VERSION 5.7 ;
  NOWIREEXTENSIONATPIN ON ;
  DIVIDERCHAR "/" ;
  BUSBITCHARS "[]" ;
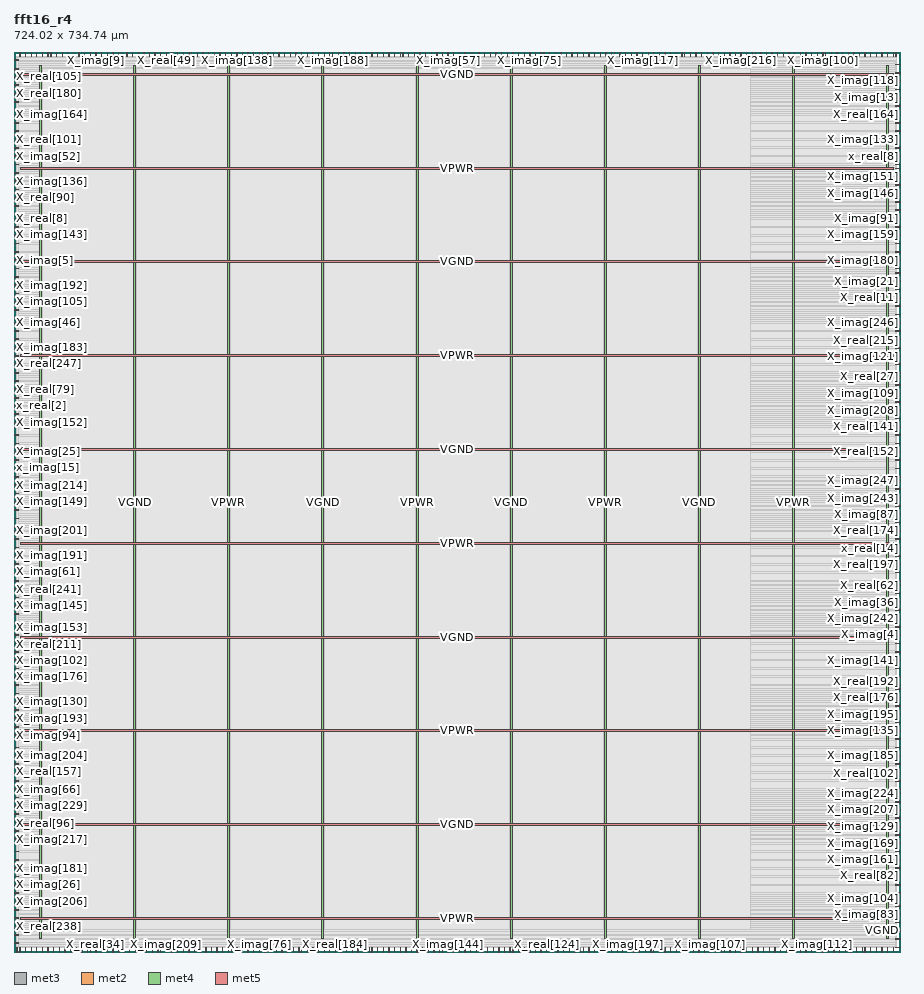
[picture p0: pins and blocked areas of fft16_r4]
MACRO fft16_r4
  CLASS BLOCK ;
  FOREIGN fft16_r4 ;
  ORIGIN 0.000 0.000 ;
  SIZE 724.020 BY 734.740 ;
  PIN X_imag[0]
    DIRECTION OUTPUT TRISTATE ;
    USE SIGNAL ;
    PORT
      LAYER met3 ;
        RECT 0.000 302.640 4.000 303.240 ;
    END
  END X_imag[0]
  PIN X_imag[100]
    DIRECTION OUTPUT TRISTATE ;
    USE SIGNAL ;
    PORT
      LAYER met2 ;
        RECT 660.190 730.740 660.470 734.740 ;
    END
  END X_imag[100]
  PIN X_imag[101]
    DIRECTION OUTPUT TRISTATE ;
    USE SIGNAL ;
    PORT
      LAYER met2 ;
        RECT 149.590 730.740 149.870 734.740 ;
    END
  END X_imag[101]
  PIN X_imag[102]
    DIRECTION OUTPUT TRISTATE ;
    USE SIGNAL ;
    PORT
      LAYER met3 ;
        RECT 0.000 238.040 4.000 238.640 ;
    END
  END X_imag[102]
  PIN X_imag[103]
    DIRECTION OUTPUT TRISTATE ;
    USE SIGNAL ;
    PORT
      LAYER met2 ;
        RECT 650.990 730.740 651.270 734.740 ;
    END
  END X_imag[103]
  PIN X_imag[104]
    DIRECTION OUTPUT TRISTATE ;
    USE SIGNAL ;
    PORT
      LAYER met3 ;
        RECT 720.020 37.440 724.020 38.040 ;
    END
  END X_imag[104]
  PIN X_imag[105]
    DIRECTION OUTPUT TRISTATE ;
    USE SIGNAL ;
    PORT
      LAYER met3 ;
        RECT 0.000 530.440 4.000 531.040 ;
    END
  END X_imag[105]
  PIN X_imag[106]
    DIRECTION OUTPUT TRISTATE ;
    USE SIGNAL ;
    PORT
      LAYER met2 ;
        RECT 165.690 0.000 165.970 4.000 ;
    END
  END X_imag[106]
  PIN X_imag[107]
    DIRECTION OUTPUT TRISTATE ;
    USE SIGNAL ;
    PORT
      LAYER met2 ;
        RECT 568.190 0.000 568.470 4.000 ;
    END
  END X_imag[107]
  PIN X_imag[108]
    DIRECTION OUTPUT TRISTATE ;
    USE SIGNAL ;
    PORT
      LAYER met2 ;
        RECT 200.190 730.740 200.470 734.740 ;
    END
  END X_imag[108]
  PIN X_imag[109]
    DIRECTION OUTPUT TRISTATE ;
    USE SIGNAL ;
    PORT
      LAYER met3 ;
        RECT 720.020 455.640 724.020 456.240 ;
    END
  END X_imag[109]
  PIN X_imag[10]
    DIRECTION OUTPUT TRISTATE ;
    USE SIGNAL ;
    PORT
      LAYER met2 ;
        RECT 220.890 730.740 221.170 734.740 ;
    END
  END X_imag[10]
  PIN X_imag[110]
    DIRECTION OUTPUT TRISTATE ;
    USE SIGNAL ;
    PORT
      LAYER met2 ;
        RECT 163.390 730.740 163.670 734.740 ;
    END
  END X_imag[110]
  PIN X_imag[111]
    DIRECTION OUTPUT TRISTATE ;
    USE SIGNAL ;
    PORT
      LAYER met2 ;
        RECT 234.690 0.000 234.970 4.000 ;
    END
  END X_imag[111]
  PIN X_imag[112]
    DIRECTION OUTPUT TRISTATE ;
    USE SIGNAL ;
    PORT
      LAYER met2 ;
        RECT 655.590 0.000 655.870 4.000 ;
    END
  END X_imag[112]
  PIN X_imag[113]
    DIRECTION OUTPUT TRISTATE ;
    USE SIGNAL ;
    PORT
      LAYER met2 ;
        RECT 243.890 730.740 244.170 734.740 ;
    END
  END X_imag[113]
  PIN X_imag[114]
    DIRECTION OUTPUT TRISTATE ;
    USE SIGNAL ;
    PORT
      LAYER met2 ;
        RECT 694.690 0.000 694.970 4.000 ;
    END
  END X_imag[114]
  PIN X_imag[115]
    DIRECTION OUTPUT TRISTATE ;
    USE SIGNAL ;
    PORT
      LAYER met2 ;
        RECT 105.890 730.740 106.170 734.740 ;
    END
  END X_imag[115]
  PIN X_imag[116]
    DIRECTION OUTPUT TRISTATE ;
    USE SIGNAL ;
    PORT
      LAYER met2 ;
        RECT 257.690 730.740 257.970 734.740 ;
    END
  END X_imag[116]
  PIN X_imag[117]
    DIRECTION OUTPUT TRISTATE ;
    USE SIGNAL ;
    PORT
      LAYER met2 ;
        RECT 512.990 730.740 513.270 734.740 ;
    END
  END X_imag[117]
  PIN X_imag[118]
    DIRECTION OUTPUT TRISTATE ;
    USE SIGNAL ;
    PORT
      LAYER met3 ;
        RECT 720.020 717.440 724.020 718.040 ;
    END
  END X_imag[118]
  PIN X_imag[119]
    DIRECTION OUTPUT TRISTATE ;
    USE SIGNAL ;
    PORT
      LAYER met2 ;
        RECT 464.690 730.740 464.970 734.740 ;
    END
  END X_imag[119]
  PIN X_imag[11]
    DIRECTION OUTPUT TRISTATE ;
    USE SIGNAL ;
    PORT
      LAYER met2 ;
        RECT 570.490 730.740 570.770 734.740 ;
    END
  END X_imag[11]
  PIN X_imag[120]
    DIRECTION OUTPUT TRISTATE ;
    USE SIGNAL ;
    PORT
      LAYER met2 ;
        RECT 430.190 0.000 430.470 4.000 ;
    END
  END X_imag[120]
  PIN X_imag[121]
    DIRECTION OUTPUT TRISTATE ;
    USE SIGNAL ;
    PORT
      LAYER met3 ;
        RECT 720.020 486.240 724.020 486.840 ;
    END
  END X_imag[121]
  PIN X_imag[122]
    DIRECTION OUTPUT TRISTATE ;
    USE SIGNAL ;
    PORT
      LAYER met2 ;
        RECT 556.690 730.740 556.970 734.740 ;
    END
  END X_imag[122]
  PIN X_imag[123]
    DIRECTION OUTPUT TRISTATE ;
    USE SIGNAL ;
    PORT
      LAYER met2 ;
        RECT 598.090 0.000 598.370 4.000 ;
    END
  END X_imag[123]
  PIN X_imag[124]
    DIRECTION OUTPUT TRISTATE ;
    USE SIGNAL ;
    PORT
      LAYER met2 ;
        RECT 588.890 0.000 589.170 4.000 ;
    END
  END X_imag[124]
  PIN X_imag[125]
    DIRECTION OUTPUT TRISTATE ;
    USE SIGNAL ;
    PORT
      LAYER met2 ;
        RECT 540.590 730.740 540.870 734.740 ;
    END
  END X_imag[125]
  PIN X_imag[126]
    DIRECTION OUTPUT TRISTATE ;
    USE SIGNAL ;
    PORT
      LAYER met3 ;
        RECT 720.020 47.640 724.020 48.240 ;
    END
  END X_imag[126]
  PIN X_imag[127]
    DIRECTION OUTPUT TRISTATE ;
    USE SIGNAL ;
    PORT
      LAYER met2 ;
        RECT 18.490 730.740 18.770 734.740 ;
    END
  END X_imag[127]
  PIN X_imag[128]
    DIRECTION OUTPUT TRISTATE ;
    USE SIGNAL ;
    PORT
      LAYER met2 ;
        RECT 473.890 730.740 474.170 734.740 ;
    END
  END X_imag[128]
  PIN X_imag[129]
    DIRECTION OUTPUT TRISTATE ;
    USE SIGNAL ;
    PORT
      LAYER met3 ;
        RECT 720.020 102.040 724.020 102.640 ;
    END
  END X_imag[129]
  PIN X_imag[12]
    DIRECTION OUTPUT TRISTATE ;
    USE SIGNAL ;
    PORT
      LAYER met2 ;
        RECT 4.690 730.740 4.970 734.740 ;
    END
  END X_imag[12]
  PIN X_imag[130]
    DIRECTION OUTPUT TRISTATE ;
    USE SIGNAL ;
    PORT
      LAYER met3 ;
        RECT 0.000 204.040 4.000 204.640 ;
    END
  END X_imag[130]
  PIN X_imag[131]
    DIRECTION OUTPUT TRISTATE ;
    USE SIGNAL ;
    PORT
      LAYER met3 ;
        RECT 0.000 112.240 4.000 112.840 ;
    END
  END X_imag[131]
  PIN X_imag[132]
    DIRECTION OUTPUT TRISTATE ;
    USE SIGNAL ;
    PORT
      LAYER met2 ;
        RECT 535.990 730.740 536.270 734.740 ;
    END
  END X_imag[132]
  PIN X_imag[133]
    DIRECTION OUTPUT TRISTATE ;
    USE SIGNAL ;
    PORT
      LAYER met3 ;
        RECT 720.020 663.040 724.020 663.640 ;
    END
  END X_imag[133]
  PIN X_imag[134]
    DIRECTION OUTPUT TRISTATE ;
    USE SIGNAL ;
    PORT
      LAYER met2 ;
        RECT 276.090 0.000 276.370 4.000 ;
    END
  END X_imag[134]
  PIN X_imag[135]
    DIRECTION OUTPUT TRISTATE ;
    USE SIGNAL ;
    PORT
      LAYER met3 ;
        RECT 720.020 180.240 724.020 180.840 ;
    END
  END X_imag[135]
  PIN X_imag[136]
    DIRECTION OUTPUT TRISTATE ;
    USE SIGNAL ;
    PORT
      LAYER met3 ;
        RECT 0.000 622.240 4.000 622.840 ;
    END
  END X_imag[136]
  PIN X_imag[137]
    DIRECTION OUTPUT TRISTATE ;
    USE SIGNAL ;
    PORT
      LAYER met2 ;
        RECT 616.490 0.000 616.770 4.000 ;
    END
  END X_imag[137]
  PIN X_imag[138]
    DIRECTION OUTPUT TRISTATE ;
    USE SIGNAL ;
    PORT
      LAYER met2 ;
        RECT 181.790 730.740 182.070 734.740 ;
    END
  END X_imag[138]
  PIN X_imag[139]
    DIRECTION OUTPUT TRISTATE ;
    USE SIGNAL ;
    PORT
      LAYER met2 ;
        RECT 207.090 730.740 207.370 734.740 ;
    END
  END X_imag[139]
  PIN X_imag[13]
    DIRECTION OUTPUT TRISTATE ;
    USE SIGNAL ;
    PORT
      LAYER met3 ;
        RECT 720.020 703.840 724.020 704.440 ;
    END
  END X_imag[13]
  PIN X_imag[140]
    DIRECTION OUTPUT TRISTATE ;
    USE SIGNAL ;
    PORT
      LAYER met3 ;
        RECT 720.020 88.440 724.020 89.040 ;
    END
  END X_imag[140]
  PIN X_imag[141]
    DIRECTION OUTPUT TRISTATE ;
    USE SIGNAL ;
    PORT
      LAYER met3 ;
        RECT 720.020 238.040 724.020 238.640 ;
    END
  END X_imag[141]
  PIN X_imag[142]
    DIRECTION OUTPUT TRISTATE ;
    USE SIGNAL ;
    PORT
      LAYER met2 ;
        RECT 223.190 0.000 223.470 4.000 ;
    END
  END X_imag[142]
  PIN X_imag[143]
    DIRECTION OUTPUT TRISTATE ;
    USE SIGNAL ;
    PORT
      LAYER met3 ;
        RECT 0.000 591.640 4.000 592.240 ;
    END
  END X_imag[143]
  PIN X_imag[144]
    DIRECTION OUTPUT TRISTATE ;
    USE SIGNAL ;
    PORT
      LAYER met2 ;
        RECT 354.290 0.000 354.570 4.000 ;
    END
  END X_imag[144]
  PIN X_imag[145]
    DIRECTION OUTPUT TRISTATE ;
    USE SIGNAL ;
    PORT
      LAYER met3 ;
        RECT 0.000 282.240 4.000 282.840 ;
    END
  END X_imag[145]
  PIN X_imag[146]
    DIRECTION OUTPUT TRISTATE ;
    USE SIGNAL ;
    PORT
      LAYER met3 ;
        RECT 720.020 618.840 724.020 619.440 ;
    END
  END X_imag[146]
  PIN X_imag[147]
    DIRECTION OUTPUT TRISTATE ;
    USE SIGNAL ;
    PORT
      LAYER met2 ;
        RECT 248.490 730.740 248.770 734.740 ;
    END
  END X_imag[147]
  PIN X_imag[148]
    DIRECTION OUTPUT TRISTATE ;
    USE SIGNAL ;
    PORT
      LAYER met2 ;
        RECT 506.090 0.000 506.370 4.000 ;
    END
  END X_imag[148]
  PIN X_imag[149]
    DIRECTION OUTPUT TRISTATE ;
    USE SIGNAL ;
    PORT
      LAYER met3 ;
        RECT 0.000 367.240 4.000 367.840 ;
    END
  END X_imag[149]
  PIN X_imag[14]
    DIRECTION OUTPUT TRISTATE ;
    USE SIGNAL ;
    PORT
      LAYER met2 ;
        RECT 460.090 730.740 460.370 734.740 ;
    END
  END X_imag[14]
  PIN X_imag[150]
    DIRECTION OUTPUT TRISTATE ;
    USE SIGNAL ;
    PORT
      LAYER met2 ;
        RECT 676.290 730.740 676.570 734.740 ;
    END
  END X_imag[150]
  PIN X_imag[151]
    DIRECTION OUTPUT TRISTATE ;
    USE SIGNAL ;
    PORT
      LAYER met3 ;
        RECT 720.020 632.440 724.020 633.040 ;
    END
  END X_imag[151]
  PIN X_imag[152]
    DIRECTION OUTPUT TRISTATE ;
    USE SIGNAL ;
    PORT
      LAYER met3 ;
        RECT 0.000 431.840 4.000 432.440 ;
    END
  END X_imag[152]
  PIN X_imag[153]
    DIRECTION OUTPUT TRISTATE ;
    USE SIGNAL ;
    PORT
      LAYER met3 ;
        RECT 0.000 258.440 4.000 259.040 ;
    END
  END X_imag[153]
  PIN X_imag[154]
    DIRECTION OUTPUT TRISTATE ;
    USE SIGNAL ;
    PORT
      LAYER met2 ;
        RECT 34.590 730.740 34.870 734.740 ;
    END
  END X_imag[154]
  PIN X_imag[155]
    DIRECTION OUTPUT TRISTATE ;
    USE SIGNAL ;
    PORT
      LAYER met2 ;
        RECT 266.890 0.000 267.170 4.000 ;
    END
  END X_imag[155]
  PIN X_imag[156]
    DIRECTION OUTPUT TRISTATE ;
    USE SIGNAL ;
    PORT
      LAYER met2 ;
        RECT 535.990 0.000 536.270 4.000 ;
    END
  END X_imag[156]
  PIN X_imag[157]
    DIRECTION OUTPUT TRISTATE ;
    USE SIGNAL ;
    PORT
      LAYER met3 ;
        RECT 0.000 132.640 4.000 133.240 ;
    END
  END X_imag[157]
  PIN X_imag[158]
    DIRECTION OUTPUT TRISTATE ;
    USE SIGNAL ;
    PORT
      LAYER met2 ;
        RECT 142.690 0.000 142.970 4.000 ;
    END
  END X_imag[158]
  PIN X_imag[159]
    DIRECTION OUTPUT TRISTATE ;
    USE SIGNAL ;
    PORT
      LAYER met3 ;
        RECT 720.020 591.640 724.020 592.240 ;
    END
  END X_imag[159]
  PIN X_imag[15]
    DIRECTION OUTPUT TRISTATE ;
    USE SIGNAL ;
    PORT
      LAYER met2 ;
        RECT 9.290 730.740 9.570 734.740 ;
    END
  END X_imag[15]
  PIN X_imag[160]
    DIRECTION OUTPUT TRISTATE ;
    USE SIGNAL ;
    PORT
      LAYER met2 ;
        RECT 662.490 730.740 662.770 734.740 ;
    END
  END X_imag[160]
  PIN X_imag[161]
    DIRECTION OUTPUT TRISTATE ;
    USE SIGNAL ;
    PORT
      LAYER met3 ;
        RECT 720.020 74.840 724.020 75.440 ;
    END
  END X_imag[161]
  PIN X_imag[162]
    DIRECTION OUTPUT TRISTATE ;
    USE SIGNAL ;
    PORT
      LAYER met3 ;
        RECT 720.020 578.040 724.020 578.640 ;
    END
  END X_imag[162]
  PIN X_imag[163]
    DIRECTION OUTPUT TRISTATE ;
    USE SIGNAL ;
    PORT
      LAYER met3 ;
        RECT 720.020 3.440 724.020 4.040 ;
    END
  END X_imag[163]
  PIN X_imag[164]
    DIRECTION OUTPUT TRISTATE ;
    USE SIGNAL ;
    PORT
      LAYER met3 ;
        RECT 0.000 683.440 4.000 684.040 ;
    END
  END X_imag[164]
  PIN X_imag[165]
    DIRECTION OUTPUT TRISTATE ;
    USE SIGNAL ;
    PORT
      LAYER met2 ;
        RECT 584.290 730.740 584.570 734.740 ;
    END
  END X_imag[165]
  PIN X_imag[166]
    DIRECTION OUTPUT TRISTATE ;
    USE SIGNAL ;
    PORT
      LAYER met2 ;
        RECT 531.390 0.000 531.670 4.000 ;
    END
  END X_imag[166]
  PIN X_imag[167]
    DIRECTION OUTPUT TRISTATE ;
    USE SIGNAL ;
    PORT
      LAYER met3 ;
        RECT 720.020 302.640 724.020 303.240 ;
    END
  END X_imag[167]
  PIN X_imag[168]
    DIRECTION OUTPUT TRISTATE ;
    USE SIGNAL ;
    PORT
      LAYER met2 ;
        RECT 450.890 730.740 451.170 734.740 ;
    END
  END X_imag[168]
  PIN X_imag[169]
    DIRECTION OUTPUT TRISTATE ;
    USE SIGNAL ;
    PORT
      LAYER met3 ;
        RECT 720.020 81.640 724.020 82.240 ;
    END
  END X_imag[169]
  PIN X_imag[16]
    DIRECTION OUTPUT TRISTATE ;
    USE SIGNAL ;
    PORT
      LAYER met3 ;
        RECT 720.020 479.440 724.020 480.040 ;
    END
  END X_imag[16]
  PIN X_imag[170]
    DIRECTION OUTPUT TRISTATE ;
    USE SIGNAL ;
    PORT
      LAYER met2 ;
        RECT 611.890 0.000 612.170 4.000 ;
    END
  END X_imag[170]
  PIN X_imag[171]
    DIRECTION OUTPUT TRISTATE ;
    USE SIGNAL ;
    PORT
      LAYER met3 ;
        RECT 720.020 676.640 724.020 677.240 ;
    END
  END X_imag[171]
  PIN X_imag[172]
    DIRECTION OUTPUT TRISTATE ;
    USE SIGNAL ;
    PORT
      LAYER met2 ;
        RECT 172.590 730.740 172.870 734.740 ;
    END
  END X_imag[172]
  PIN X_imag[173]
    DIRECTION OUTPUT TRISTATE ;
    USE SIGNAL ;
    PORT
      LAYER met3 ;
        RECT 720.020 10.240 724.020 10.840 ;
    END
  END X_imag[173]
  PIN X_imag[174]
    DIRECTION OUTPUT TRISTATE ;
    USE SIGNAL ;
    PORT
      LAYER met2 ;
        RECT 717.690 730.740 717.970 734.740 ;
    END
  END X_imag[174]
  PIN X_imag[175]
    DIRECTION OUTPUT TRISTATE ;
    USE SIGNAL ;
    PORT
      LAYER met3 ;
        RECT 720.020 309.440 724.020 310.040 ;
    END
  END X_imag[175]
  PIN X_imag[176]
    DIRECTION OUTPUT TRISTATE ;
    USE SIGNAL ;
    PORT
      LAYER met3 ;
        RECT 0.000 224.440 4.000 225.040 ;
    END
  END X_imag[176]
  PIN X_imag[177]
    DIRECTION OUTPUT TRISTATE ;
    USE SIGNAL ;
    PORT
      LAYER met3 ;
        RECT 0.000 506.640 4.000 507.240 ;
    END
  END X_imag[177]
  PIN X_imag[178]
    DIRECTION OUTPUT TRISTATE ;
    USE SIGNAL ;
    PORT
      LAYER met2 ;
        RECT 23.090 0.000 23.370 4.000 ;
    END
  END X_imag[178]
  PIN X_imag[179]
    DIRECTION OUTPUT TRISTATE ;
    USE SIGNAL ;
    PORT
      LAYER met3 ;
        RECT 0.000 523.640 4.000 524.240 ;
    END
  END X_imag[179]
  PIN X_imag[17]
    DIRECTION OUTPUT TRISTATE ;
    USE SIGNAL ;
    PORT
      LAYER met2 ;
        RECT 278.390 730.740 278.670 734.740 ;
    END
  END X_imag[17]
  PIN X_imag[180]
    DIRECTION OUTPUT TRISTATE ;
    USE SIGNAL ;
    PORT
      LAYER met3 ;
        RECT 720.020 564.440 724.020 565.040 ;
    END
  END X_imag[180]
  PIN X_imag[181]
    DIRECTION OUTPUT TRISTATE ;
    USE SIGNAL ;
    PORT
      LAYER met3 ;
        RECT 0.000 68.040 4.000 68.640 ;
    END
  END X_imag[181]
  PIN X_imag[182]
    DIRECTION OUTPUT TRISTATE ;
    USE SIGNAL ;
    PORT
      LAYER met3 ;
        RECT 720.020 669.840 724.020 670.440 ;
    END
  END X_imag[182]
  PIN X_imag[183]
    DIRECTION OUTPUT TRISTATE ;
    USE SIGNAL ;
    PORT
      LAYER met3 ;
        RECT 0.000 493.040 4.000 493.640 ;
    END
  END X_imag[183]
  PIN X_imag[184]
    DIRECTION OUTPUT TRISTATE ;
    USE SIGNAL ;
    PORT
      LAYER met3 ;
        RECT 720.020 506.640 724.020 507.240 ;
    END
  END X_imag[184]
  PIN X_imag[185]
    DIRECTION OUTPUT TRISTATE ;
    USE SIGNAL ;
    PORT
      LAYER met3 ;
        RECT 720.020 159.840 724.020 160.440 ;
    END
  END X_imag[185]
  PIN X_imag[186]
    DIRECTION OUTPUT TRISTATE ;
    USE SIGNAL ;
    PORT
      LAYER met2 ;
        RECT 248.490 0.000 248.770 4.000 ;
    END
  END X_imag[186]
  PIN X_imag[187]
    DIRECTION OUTPUT TRISTATE ;
    USE SIGNAL ;
    PORT
      LAYER met2 ;
        RECT 384.190 730.740 384.470 734.740 ;
    END
  END X_imag[187]
  PIN X_imag[188]
    DIRECTION OUTPUT TRISTATE ;
    USE SIGNAL ;
    PORT
      LAYER met2 ;
        RECT 259.990 730.740 260.270 734.740 ;
    END
  END X_imag[188]
  PIN X_imag[189]
    DIRECTION OUTPUT TRISTATE ;
    USE SIGNAL ;
    PORT
      LAYER met3 ;
        RECT 720.020 166.640 724.020 167.240 ;
    END
  END X_imag[189]
  PIN X_imag[18]
    DIRECTION OUTPUT TRISTATE ;
    USE SIGNAL ;
    PORT
      LAYER met2 ;
        RECT 23.090 730.740 23.370 734.740 ;
    END
  END X_imag[18]
  PIN X_imag[190]
    DIRECTION OUTPUT TRISTATE ;
    USE SIGNAL ;
    PORT
      LAYER met3 ;
        RECT 720.020 200.640 724.020 201.240 ;
    END
  END X_imag[190]
  PIN X_imag[191]
    DIRECTION OUTPUT TRISTATE ;
    USE SIGNAL ;
    PORT
      LAYER met3 ;
        RECT 0.000 323.040 4.000 323.640 ;
    END
  END X_imag[191]
  PIN X_imag[192]
    DIRECTION OUTPUT TRISTATE ;
    USE SIGNAL ;
    PORT
      LAYER met3 ;
        RECT 0.000 537.240 4.000 537.840 ;
    END
  END X_imag[192]
  PIN X_imag[193]
    DIRECTION OUTPUT TRISTATE ;
    USE SIGNAL ;
    PORT
      LAYER met3 ;
        RECT 0.000 190.440 4.000 191.040 ;
    END
  END X_imag[193]
  PIN X_imag[194]
    DIRECTION OUTPUT TRISTATE ;
    USE SIGNAL ;
    PORT
      LAYER met2 ;
        RECT 75.990 730.740 76.270 734.740 ;
    END
  END X_imag[194]
  PIN X_imag[195]
    DIRECTION OUTPUT TRISTATE ;
    USE SIGNAL ;
    PORT
      LAYER met3 ;
        RECT 720.020 193.840 724.020 194.440 ;
    END
  END X_imag[195]
  PIN X_imag[196]
    DIRECTION OUTPUT TRISTATE ;
    USE SIGNAL ;
    PORT
      LAYER met2 ;
        RECT 292.190 0.000 292.470 4.000 ;
    END
  END X_imag[196]
  PIN X_imag[197]
    DIRECTION OUTPUT TRISTATE ;
    USE SIGNAL ;
    PORT
      LAYER met2 ;
        RECT 501.490 0.000 501.770 4.000 ;
    END
  END X_imag[197]
  PIN X_imag[198]
    DIRECTION OUTPUT TRISTATE ;
    USE SIGNAL ;
    PORT
      LAYER met2 ;
        RECT 483.090 730.740 483.370 734.740 ;
    END
  END X_imag[198]
  PIN X_imag[199]
    DIRECTION OUTPUT TRISTATE ;
    USE SIGNAL ;
    PORT
      LAYER met2 ;
        RECT 487.690 0.000 487.970 4.000 ;
    END
  END X_imag[199]
  PIN X_imag[19]
    DIRECTION OUTPUT TRISTATE ;
    USE SIGNAL ;
    PORT
      LAYER met2 ;
        RECT 430.190 730.740 430.470 734.740 ;
    END
  END X_imag[19]
  PIN X_imag[1]
    DIRECTION OUTPUT TRISTATE ;
    USE SIGNAL ;
    PORT
      LAYER met2 ;
        RECT 685.490 730.740 685.770 734.740 ;
    END
  END X_imag[1]
  PIN X_imag[200]
    DIRECTION OUTPUT TRISTATE ;
    USE SIGNAL ;
    PORT
      LAYER met2 ;
        RECT 552.090 730.740 552.370 734.740 ;
    END
  END X_imag[200]
  PIN X_imag[201]
    DIRECTION OUTPUT TRISTATE ;
    USE SIGNAL ;
    PORT
      LAYER met3 ;
        RECT 0.000 343.440 4.000 344.040 ;
    END
  END X_imag[201]
  PIN X_imag[202]
    DIRECTION OUTPUT TRISTATE ;
    USE SIGNAL ;
    PORT
      LAYER met2 ;
        RECT 13.890 0.000 14.170 4.000 ;
    END
  END X_imag[202]
  PIN X_imag[203]
    DIRECTION OUTPUT TRISTATE ;
    USE SIGNAL ;
    PORT
      LAYER met2 ;
        RECT 4.690 0.000 4.970 4.000 ;
    END
  END X_imag[203]
  PIN X_imag[204]
    DIRECTION OUTPUT TRISTATE ;
    USE SIGNAL ;
    PORT
      LAYER met3 ;
        RECT 0.000 159.840 4.000 160.440 ;
    END
  END X_imag[204]
  PIN X_imag[205]
    DIRECTION OUTPUT TRISTATE ;
    USE SIGNAL ;
    PORT
      LAYER met2 ;
        RECT 289.890 0.000 290.170 4.000 ;
    END
  END X_imag[205]
  PIN X_imag[206]
    DIRECTION OUTPUT TRISTATE ;
    USE SIGNAL ;
    PORT
      LAYER met3 ;
        RECT 0.000 40.840 4.000 41.440 ;
    END
  END X_imag[206]
  PIN X_imag[207]
    DIRECTION OUTPUT TRISTATE ;
    USE SIGNAL ;
    PORT
      LAYER met3 ;
        RECT 720.020 115.640 724.020 116.240 ;
    END
  END X_imag[207]
  PIN X_imag[208]
    DIRECTION OUTPUT TRISTATE ;
    USE SIGNAL ;
    PORT
      LAYER met3 ;
        RECT 720.020 442.040 724.020 442.640 ;
    END
  END X_imag[208]
  PIN X_imag[209]
    DIRECTION OUTPUT TRISTATE ;
    USE SIGNAL ;
    PORT
      LAYER met2 ;
        RECT 124.290 0.000 124.570 4.000 ;
    END
  END X_imag[209]
  PIN X_imag[20]
    DIRECTION OUTPUT TRISTATE ;
    USE SIGNAL ;
    PORT
      LAYER met2 ;
        RECT 174.890 0.000 175.170 4.000 ;
    END
  END X_imag[20]
  PIN X_imag[210]
    DIRECTION OUTPUT TRISTATE ;
    USE SIGNAL ;
    PORT
      LAYER met2 ;
        RECT 211.690 730.740 211.970 734.740 ;
    END
  END X_imag[210]
  PIN X_imag[211]
    DIRECTION OUTPUT TRISTATE ;
    USE SIGNAL ;
    PORT
      LAYER met2 ;
        RECT 455.490 730.740 455.770 734.740 ;
    END
  END X_imag[211]
  PIN X_imag[212]
    DIRECTION OUTPUT TRISTATE ;
    USE SIGNAL ;
    PORT
      LAYER met3 ;
        RECT 720.020 462.440 724.020 463.040 ;
    END
  END X_imag[212]
  PIN X_imag[213]
    DIRECTION OUTPUT TRISTATE ;
    USE SIGNAL ;
    PORT
      LAYER met3 ;
        RECT 0.000 360.440 4.000 361.040 ;
    END
  END X_imag[213]
  PIN X_imag[214]
    DIRECTION OUTPUT TRISTATE ;
    USE SIGNAL ;
    PORT
      LAYER met3 ;
        RECT 0.000 374.040 4.000 374.640 ;
    END
  END X_imag[214]
  PIN X_imag[215]
    DIRECTION OUTPUT TRISTATE ;
    USE SIGNAL ;
    PORT
      LAYER met2 ;
        RECT 128.890 730.740 129.170 734.740 ;
    END
  END X_imag[215]
  PIN X_imag[216]
    DIRECTION OUTPUT TRISTATE ;
    USE SIGNAL ;
    PORT
      LAYER met2 ;
        RECT 593.490 730.740 593.770 734.740 ;
    END
  END X_imag[216]
  PIN X_imag[217]
    DIRECTION OUTPUT TRISTATE ;
    USE SIGNAL ;
    PORT
      LAYER met3 ;
        RECT 0.000 91.840 4.000 92.440 ;
    END
  END X_imag[217]
  PIN X_imag[218]
    DIRECTION OUTPUT TRISTATE ;
    USE SIGNAL ;
    PORT
      LAYER met3 ;
        RECT 0.000 295.840 4.000 296.440 ;
    END
  END X_imag[218]
  PIN X_imag[219]
    DIRECTION OUTPUT TRISTATE ;
    USE SIGNAL ;
    PORT
      LAYER met2 ;
        RECT 602.690 0.000 602.970 4.000 ;
    END
  END X_imag[219]
  PIN X_imag[21]
    DIRECTION OUTPUT TRISTATE ;
    USE SIGNAL ;
    PORT
      LAYER met3 ;
        RECT 720.020 547.440 724.020 548.040 ;
    END
  END X_imag[21]
  PIN X_imag[220]
    DIRECTION OUTPUT TRISTATE ;
    USE SIGNAL ;
    PORT
      LAYER met3 ;
        RECT 0.000 353.640 4.000 354.240 ;
    END
  END X_imag[220]
  PIN X_imag[221]
    DIRECTION OUTPUT TRISTATE ;
    USE SIGNAL ;
    PORT
      LAYER met2 ;
        RECT 282.990 730.740 283.270 734.740 ;
    END
  END X_imag[221]
  PIN X_imag[222]
    DIRECTION OUTPUT TRISTATE ;
    USE SIGNAL ;
    PORT
      LAYER met2 ;
        RECT 280.690 0.000 280.970 4.000 ;
    END
  END X_imag[222]
  PIN X_imag[223]
    DIRECTION OUTPUT TRISTATE ;
    USE SIGNAL ;
    PORT
      LAYER met2 ;
        RECT 349.690 730.740 349.970 734.740 ;
    END
  END X_imag[223]
  PIN X_imag[224]
    DIRECTION OUTPUT TRISTATE ;
    USE SIGNAL ;
    PORT
      LAYER met3 ;
        RECT 720.020 129.240 724.020 129.840 ;
    END
  END X_imag[224]
  PIN X_imag[225]
    DIRECTION OUTPUT TRISTATE ;
    USE SIGNAL ;
    PORT
      LAYER met3 ;
        RECT 720.020 23.840 724.020 24.440 ;
    END
  END X_imag[225]
  PIN X_imag[226]
    DIRECTION OUTPUT TRISTATE ;
    USE SIGNAL ;
    PORT
      LAYER met2 ;
        RECT 202.490 730.740 202.770 734.740 ;
    END
  END X_imag[226]
  PIN X_imag[227]
    DIRECTION OUTPUT TRISTATE ;
    USE SIGNAL ;
    PORT
      LAYER met3 ;
        RECT 720.020 639.240 724.020 639.840 ;
    END
  END X_imag[227]
  PIN X_imag[228]
    DIRECTION OUTPUT TRISTATE ;
    USE SIGNAL ;
    PORT
      LAYER met2 ;
        RECT 416.390 730.740 416.670 734.740 ;
    END
  END X_imag[228]
  PIN X_imag[229]
    DIRECTION OUTPUT TRISTATE ;
    USE SIGNAL ;
    PORT
      LAYER met3 ;
        RECT 0.000 119.040 4.000 119.640 ;
    END
  END X_imag[229]
  PIN X_imag[22]
    DIRECTION OUTPUT TRISTATE ;
    USE SIGNAL ;
    PORT
      LAYER met3 ;
        RECT 0.000 336.640 4.000 337.240 ;
    END
  END X_imag[22]
  PIN X_imag[230]
    DIRECTION OUTPUT TRISTATE ;
    USE SIGNAL ;
    PORT
      LAYER met2 ;
        RECT 27.690 0.000 27.970 4.000 ;
    END
  END X_imag[230]
  PIN X_imag[231]
    DIRECTION OUTPUT TRISTATE ;
    USE SIGNAL ;
    PORT
      LAYER met2 ;
        RECT 489.990 730.740 490.270 734.740 ;
    END
  END X_imag[231]
  PIN X_imag[232]
    DIRECTION OUTPUT TRISTATE ;
    USE SIGNAL ;
    PORT
      LAYER met3 ;
        RECT 720.020 571.240 724.020 571.840 ;
    END
  END X_imag[232]
  PIN X_imag[233]
    DIRECTION OUTPUT TRISTATE ;
    USE SIGNAL ;
    PORT
      LAYER met2 ;
        RECT 305.990 0.000 306.270 4.000 ;
    END
  END X_imag[233]
  PIN X_imag[234]
    DIRECTION OUTPUT TRISTATE ;
    USE SIGNAL ;
    PORT
      LAYER met2 ;
        RECT 342.790 0.000 343.070 4.000 ;
    END
  END X_imag[234]
  PIN X_imag[235]
    DIRECTION OUTPUT TRISTATE ;
    USE SIGNAL ;
    PORT
      LAYER met2 ;
        RECT 379.590 730.740 379.870 734.740 ;
    END
  END X_imag[235]
  PIN X_imag[236]
    DIRECTION OUTPUT TRISTATE ;
    USE SIGNAL ;
    PORT
      LAYER met2 ;
        RECT 439.390 0.000 439.670 4.000 ;
    END
  END X_imag[236]
  PIN X_imag[237]
    DIRECTION OUTPUT TRISTATE ;
    USE SIGNAL ;
    PORT
      LAYER met2 ;
        RECT 2.390 0.000 2.670 4.000 ;
    END
  END X_imag[237]
  PIN X_imag[238]
    DIRECTION OUTPUT TRISTATE ;
    USE SIGNAL ;
    PORT
      LAYER met2 ;
        RECT 50.690 0.000 50.970 4.000 ;
    END
  END X_imag[238]
  PIN X_imag[239]
    DIRECTION OUTPUT TRISTATE ;
    USE SIGNAL ;
    PORT
      LAYER met2 ;
        RECT 103.590 0.000 103.870 4.000 ;
    END
  END X_imag[239]
  PIN X_imag[23]
    DIRECTION OUTPUT TRISTATE ;
    USE SIGNAL ;
    PORT
      LAYER met3 ;
        RECT 0.000 251.640 4.000 252.240 ;
    END
  END X_imag[23]
  PIN X_imag[240]
    DIRECTION OUTPUT TRISTATE ;
    USE SIGNAL ;
    PORT
      LAYER met3 ;
        RECT 0.000 6.840 4.000 7.440 ;
    END
  END X_imag[240]
  PIN X_imag[241]
    DIRECTION OUTPUT TRISTATE ;
    USE SIGNAL ;
    PORT
      LAYER met3 ;
        RECT 720.020 625.640 724.020 626.240 ;
    END
  END X_imag[241]
  PIN X_imag[242]
    DIRECTION OUTPUT TRISTATE ;
    USE SIGNAL ;
    PORT
      LAYER met3 ;
        RECT 720.020 272.040 724.020 272.640 ;
    END
  END X_imag[242]
  PIN X_imag[243]
    DIRECTION OUTPUT TRISTATE ;
    USE SIGNAL ;
    PORT
      LAYER met3 ;
        RECT 720.020 363.840 724.020 364.440 ;
    END
  END X_imag[243]
  PIN X_imag[244]
    DIRECTION OUTPUT TRISTATE ;
    USE SIGNAL ;
    PORT
      LAYER met2 ;
        RECT 80.590 730.740 80.870 734.740 ;
    END
  END X_imag[244]
  PIN X_imag[245]
    DIRECTION OUTPUT TRISTATE ;
    USE SIGNAL ;
    PORT
      LAYER met2 ;
        RECT 678.590 0.000 678.870 4.000 ;
    END
  END X_imag[245]
  PIN X_imag[246]
    DIRECTION OUTPUT TRISTATE ;
    USE SIGNAL ;
    PORT
      LAYER met3 ;
        RECT 720.020 513.440 724.020 514.040 ;
    END
  END X_imag[246]
  PIN X_imag[247]
    DIRECTION OUTPUT TRISTATE ;
    USE SIGNAL ;
    PORT
      LAYER met3 ;
        RECT 720.020 384.240 724.020 384.840 ;
    END
  END X_imag[247]
  PIN X_imag[248]
    DIRECTION OUTPUT TRISTATE ;
    USE SIGNAL ;
    PORT
      LAYER met2 ;
        RECT 227.790 0.000 228.070 4.000 ;
    END
  END X_imag[248]
  PIN X_imag[249]
    DIRECTION OUTPUT TRISTATE ;
    USE SIGNAL ;
    PORT
      LAYER met2 ;
        RECT 483.090 0.000 483.370 4.000 ;
    END
  END X_imag[249]
  PIN X_imag[24]
    DIRECTION OUTPUT TRISTATE ;
    USE SIGNAL ;
    PORT
      LAYER met2 ;
        RECT 216.290 730.740 216.570 734.740 ;
    END
  END X_imag[24]
  PIN X_imag[250]
    DIRECTION OUTPUT TRISTATE ;
    USE SIGNAL ;
    PORT
      LAYER met2 ;
        RECT 641.790 0.000 642.070 4.000 ;
    END
  END X_imag[250]
  PIN X_imag[251]
    DIRECTION OUTPUT TRISTATE ;
    USE SIGNAL ;
    PORT
      LAYER met2 ;
        RECT 358.890 730.740 359.170 734.740 ;
    END
  END X_imag[251]
  PIN X_imag[252]
    DIRECTION OUTPUT TRISTATE ;
    USE SIGNAL ;
    PORT
      LAYER met2 ;
        RECT 469.290 0.000 469.570 4.000 ;
    END
  END X_imag[252]
  PIN X_imag[253]
    DIRECTION OUTPUT TRISTATE ;
    USE SIGNAL ;
    PORT
      LAYER met2 ;
        RECT 345.090 730.740 345.370 734.740 ;
    END
  END X_imag[253]
  PIN X_imag[254]
    DIRECTION OUTPUT TRISTATE ;
    USE SIGNAL ;
    PORT
      LAYER met2 ;
        RECT 368.090 0.000 368.370 4.000 ;
    END
  END X_imag[254]
  PIN X_imag[255]
    DIRECTION OUTPUT TRISTATE ;
    USE SIGNAL ;
    PORT
      LAYER met2 ;
        RECT 655.590 730.740 655.870 734.740 ;
    END
  END X_imag[255]
  PIN X_imag[25]
    DIRECTION OUTPUT TRISTATE ;
    USE SIGNAL ;
    PORT
      LAYER met3 ;
        RECT 0.000 408.040 4.000 408.640 ;
    END
  END X_imag[25]
  PIN X_imag[26]
    DIRECTION OUTPUT TRISTATE ;
    USE SIGNAL ;
    PORT
      LAYER met3 ;
        RECT 0.000 54.440 4.000 55.040 ;
    END
  END X_imag[26]
  PIN X_imag[27]
    DIRECTION OUTPUT TRISTATE ;
    USE SIGNAL ;
    PORT
      LAYER met3 ;
        RECT 0.000 557.640 4.000 558.240 ;
    END
  END X_imag[27]
  PIN X_imag[28]
    DIRECTION OUTPUT TRISTATE ;
    USE SIGNAL ;
    PORT
      LAYER met2 ;
        RECT 358.890 0.000 359.170 4.000 ;
    END
  END X_imag[28]
  PIN X_imag[29]
    DIRECTION OUTPUT TRISTATE ;
    USE SIGNAL ;
    PORT
      LAYER met2 ;
        RECT 52.990 730.740 53.270 734.740 ;
    END
  END X_imag[29]
  PIN X_imag[2]
    DIRECTION OUTPUT TRISTATE ;
    USE SIGNAL ;
    PORT
      LAYER met3 ;
        RECT 0.000 275.440 4.000 276.040 ;
    END
  END X_imag[2]
  PIN X_imag[30]
    DIRECTION OUTPUT TRISTATE ;
    USE SIGNAL ;
    PORT
      LAYER met3 ;
        RECT 0.000 105.440 4.000 106.040 ;
    END
  END X_imag[30]
  PIN X_imag[31]
    DIRECTION OUTPUT TRISTATE ;
    USE SIGNAL ;
    PORT
      LAYER met2 ;
        RECT 324.390 0.000 324.670 4.000 ;
    END
  END X_imag[31]
  PIN X_imag[32]
    DIRECTION OUTPUT TRISTATE ;
    USE SIGNAL ;
    PORT
      LAYER met2 ;
        RECT 671.690 730.740 671.970 734.740 ;
    END
  END X_imag[32]
  PIN X_imag[33]
    DIRECTION OUTPUT TRISTATE ;
    USE SIGNAL ;
    PORT
      LAYER met2 ;
        RECT 510.690 0.000 510.970 4.000 ;
    END
  END X_imag[33]
  PIN X_imag[34]
    DIRECTION OUTPUT TRISTATE ;
    USE SIGNAL ;
    PORT
      LAYER met2 ;
        RECT 503.790 730.740 504.070 734.740 ;
    END
  END X_imag[34]
  PIN X_imag[35]
    DIRECTION OUTPUT TRISTATE ;
    USE SIGNAL ;
    PORT
      LAYER met2 ;
        RECT 558.990 0.000 559.270 4.000 ;
    END
  END X_imag[35]
  PIN X_imag[36]
    DIRECTION OUTPUT TRISTATE ;
    USE SIGNAL ;
    PORT
      LAYER met3 ;
        RECT 720.020 278.840 724.020 279.440 ;
    END
  END X_imag[36]
  PIN X_imag[37]
    DIRECTION OUTPUT TRISTATE ;
    USE SIGNAL ;
    PORT
      LAYER met3 ;
        RECT 0.000 438.640 4.000 439.240 ;
    END
  END X_imag[37]
  PIN X_imag[38]
    DIRECTION OUTPUT TRISTATE ;
    USE SIGNAL ;
    PORT
      LAYER met2 ;
        RECT 494.590 730.740 494.870 734.740 ;
    END
  END X_imag[38]
  PIN X_imag[39]
    DIRECTION OUTPUT TRISTATE ;
    USE SIGNAL ;
    PORT
      LAYER met2 ;
        RECT 253.090 730.740 253.370 734.740 ;
    END
  END X_imag[39]
  PIN X_imag[3]
    DIRECTION OUTPUT TRISTATE ;
    USE SIGNAL ;
    PORT
      LAYER met2 ;
        RECT 630.290 0.000 630.570 4.000 ;
    END
  END X_imag[3]
  PIN X_imag[40]
    DIRECTION OUTPUT TRISTATE ;
    USE SIGNAL ;
    PORT
      LAYER met3 ;
        RECT 0.000 74.840 4.000 75.440 ;
    END
  END X_imag[40]
  PIN X_imag[41]
    DIRECTION OUTPUT TRISTATE ;
    USE SIGNAL ;
    PORT
      LAYER met3 ;
        RECT 720.020 44.240 724.020 44.840 ;
    END
  END X_imag[41]
  PIN X_imag[42]
    DIRECTION OUTPUT TRISTATE ;
    USE SIGNAL ;
    PORT
      LAYER met2 ;
        RECT 87.490 730.740 87.770 734.740 ;
    END
  END X_imag[42]
  PIN X_imag[43]
    DIRECTION OUTPUT TRISTATE ;
    USE SIGNAL ;
    PORT
      LAYER met2 ;
        RECT 138.090 730.740 138.370 734.740 ;
    END
  END X_imag[43]
  PIN X_imag[44]
    DIRECTION OUTPUT TRISTATE ;
    USE SIGNAL ;
    PORT
      LAYER met3 ;
        RECT 0.000 584.840 4.000 585.440 ;
    END
  END X_imag[44]
  PIN X_imag[45]
    DIRECTION OUTPUT TRISTATE ;
    USE SIGNAL ;
    PORT
      LAYER met2 ;
        RECT 133.490 730.740 133.770 734.740 ;
    END
  END X_imag[45]
  PIN X_imag[46]
    DIRECTION OUTPUT TRISTATE ;
    USE SIGNAL ;
    PORT
      LAYER met3 ;
        RECT 0.000 513.440 4.000 514.040 ;
    END
  END X_imag[46]
  PIN X_imag[47]
    DIRECTION OUTPUT TRISTATE ;
    USE SIGNAL ;
    PORT
      LAYER met2 ;
        RECT 660.190 0.000 660.470 4.000 ;
    END
  END X_imag[47]
  PIN X_imag[48]
    DIRECTION OUTPUT TRISTATE ;
    USE SIGNAL ;
    PORT
      LAYER met2 ;
        RECT 411.790 0.000 412.070 4.000 ;
    END
  END X_imag[48]
  PIN X_imag[49]
    DIRECTION OUTPUT TRISTATE ;
    USE SIGNAL ;
    PORT
      LAYER met2 ;
        RECT 368.090 730.740 368.370 734.740 ;
    END
  END X_imag[49]
  PIN X_imag[4]
    DIRECTION OUTPUT TRISTATE ;
    USE SIGNAL ;
    PORT
      LAYER met3 ;
        RECT 720.020 265.240 724.020 265.840 ;
    END
  END X_imag[4]
  PIN X_imag[50]
    DIRECTION OUTPUT TRISTATE ;
    USE SIGNAL ;
    PORT
      LAYER met2 ;
        RECT 234.690 730.740 234.970 734.740 ;
    END
  END X_imag[50]
  PIN X_imag[51]
    DIRECTION OUTPUT TRISTATE ;
    USE SIGNAL ;
    PORT
      LAYER met2 ;
        RECT 499.190 730.740 499.470 734.740 ;
    END
  END X_imag[51]
  PIN X_imag[52]
    DIRECTION OUTPUT TRISTATE ;
    USE SIGNAL ;
    PORT
      LAYER met3 ;
        RECT 0.000 649.440 4.000 650.040 ;
    END
  END X_imag[52]
  PIN X_imag[53]
    DIRECTION OUTPUT TRISTATE ;
    USE SIGNAL ;
    PORT
      LAYER met2 ;
        RECT 310.590 730.740 310.870 734.740 ;
    END
  END X_imag[53]
  PIN X_imag[54]
    DIRECTION OUTPUT TRISTATE ;
    USE SIGNAL ;
    PORT
      LAYER met2 ;
        RECT 402.590 730.740 402.870 734.740 ;
    END
  END X_imag[54]
  PIN X_imag[55]
    DIRECTION OUTPUT TRISTATE ;
    USE SIGNAL ;
    PORT
      LAYER met3 ;
        RECT 720.020 557.640 724.020 558.240 ;
    END
  END X_imag[55]
  PIN X_imag[56]
    DIRECTION OUTPUT TRISTATE ;
    USE SIGNAL ;
    PORT
      LAYER met2 ;
        RECT 609.590 730.740 609.870 734.740 ;
    END
  END X_imag[56]
  PIN X_imag[57]
    DIRECTION OUTPUT TRISTATE ;
    USE SIGNAL ;
    PORT
      LAYER met2 ;
        RECT 354.290 730.740 354.570 734.740 ;
    END
  END X_imag[57]
  PIN X_imag[58]
    DIRECTION OUTPUT TRISTATE ;
    USE SIGNAL ;
    PORT
      LAYER met2 ;
        RECT 115.090 730.740 115.370 734.740 ;
    END
  END X_imag[58]
  PIN X_imag[59]
    DIRECTION OUTPUT TRISTATE ;
    USE SIGNAL ;
    PORT
      LAYER met2 ;
        RECT 110.490 730.740 110.770 734.740 ;
    END
  END X_imag[59]
  PIN X_imag[5]
    DIRECTION OUTPUT TRISTATE ;
    USE SIGNAL ;
    PORT
      LAYER met3 ;
        RECT 0.000 564.440 4.000 565.040 ;
    END
  END X_imag[5]
  PIN X_imag[60]
    DIRECTION OUTPUT TRISTATE ;
    USE SIGNAL ;
    PORT
      LAYER met2 ;
        RECT 614.190 730.740 614.470 734.740 ;
    END
  END X_imag[60]
  PIN X_imag[61]
    DIRECTION OUTPUT TRISTATE ;
    USE SIGNAL ;
    PORT
      LAYER met3 ;
        RECT 0.000 316.240 4.000 316.840 ;
    END
  END X_imag[61]
  PIN X_imag[62]
    DIRECTION OUTPUT TRISTATE ;
    USE SIGNAL ;
    PORT
      LAYER met3 ;
        RECT 720.020 710.640 724.020 711.240 ;
    END
  END X_imag[62]
  PIN X_imag[63]
    DIRECTION OUTPUT TRISTATE ;
    USE SIGNAL ;
    PORT
      LAYER met2 ;
        RECT 186.390 730.740 186.670 734.740 ;
    END
  END X_imag[63]
  PIN X_imag[64]
    DIRECTION OUTPUT TRISTATE ;
    USE SIGNAL ;
    PORT
      LAYER met2 ;
        RECT 62.190 0.000 62.470 4.000 ;
    END
  END X_imag[64]
  PIN X_imag[65]
    DIRECTION OUTPUT TRISTATE ;
    USE SIGNAL ;
    PORT
      LAYER met3 ;
        RECT 0.000 183.640 4.000 184.240 ;
    END
  END X_imag[65]
  PIN X_imag[66]
    DIRECTION OUTPUT TRISTATE ;
    USE SIGNAL ;
    PORT
      LAYER met3 ;
        RECT 0.000 125.840 4.000 126.440 ;
    END
  END X_imag[66]
  PIN X_imag[67]
    DIRECTION OUTPUT TRISTATE ;
    USE SIGNAL ;
    PORT
      LAYER met2 ;
        RECT 43.790 730.740 44.070 734.740 ;
    END
  END X_imag[67]
  PIN X_imag[68]
    DIRECTION OUTPUT TRISTATE ;
    USE SIGNAL ;
    PORT
      LAYER met2 ;
        RECT 386.490 0.000 386.770 4.000 ;
    END
  END X_imag[68]
  PIN X_imag[69]
    DIRECTION OUTPUT TRISTATE ;
    USE SIGNAL ;
    PORT
      LAYER met2 ;
        RECT 239.290 0.000 239.570 4.000 ;
    END
  END X_imag[69]
  PIN X_imag[6]
    DIRECTION OUTPUT TRISTATE ;
    USE SIGNAL ;
    PORT
      LAYER met2 ;
        RECT 393.390 730.740 393.670 734.740 ;
    END
  END X_imag[6]
  PIN X_imag[70]
    DIRECTION OUTPUT TRISTATE ;
    USE SIGNAL ;
    PORT
      LAYER met2 ;
        RECT 98.990 0.000 99.270 4.000 ;
    END
  END X_imag[70]
  PIN X_imag[71]
    DIRECTION OUTPUT TRISTATE ;
    USE SIGNAL ;
    PORT
      LAYER met2 ;
        RECT 708.490 0.000 708.770 4.000 ;
    END
  END X_imag[71]
  PIN X_imag[72]
    DIRECTION OUTPUT TRISTATE ;
    USE SIGNAL ;
    PORT
      LAYER met2 ;
        RECT 27.690 730.740 27.970 734.740 ;
    END
  END X_imag[72]
  PIN X_imag[73]
    DIRECTION OUTPUT TRISTATE ;
    USE SIGNAL ;
    PORT
      LAYER met2 ;
        RECT 437.090 730.740 437.370 734.740 ;
    END
  END X_imag[73]
  PIN X_imag[74]
    DIRECTION OUTPUT TRISTATE ;
    USE SIGNAL ;
    PORT
      LAYER met2 ;
        RECT 296.790 0.000 297.070 4.000 ;
    END
  END X_imag[74]
  PIN X_imag[75]
    DIRECTION OUTPUT TRISTATE ;
    USE SIGNAL ;
    PORT
      LAYER met2 ;
        RECT 420.990 730.740 421.270 734.740 ;
    END
  END X_imag[75]
  PIN X_imag[76]
    DIRECTION OUTPUT TRISTATE ;
    USE SIGNAL ;
    PORT
      LAYER met2 ;
        RECT 200.190 0.000 200.470 4.000 ;
    END
  END X_imag[76]
  PIN X_imag[77]
    DIRECTION OUTPUT TRISTATE ;
    USE SIGNAL ;
    PORT
      LAYER met2 ;
        RECT 48.390 730.740 48.670 734.740 ;
    END
  END X_imag[77]
  PIN X_imag[78]
    DIRECTION OUTPUT TRISTATE ;
    USE SIGNAL ;
    PORT
      LAYER met2 ;
        RECT 119.690 730.740 119.970 734.740 ;
    END
  END X_imag[78]
  PIN X_imag[79]
    DIRECTION OUTPUT TRISTATE ;
    USE SIGNAL ;
    PORT
      LAYER met2 ;
        RECT 531.390 730.740 531.670 734.740 ;
    END
  END X_imag[79]
  PIN X_imag[7]
    DIRECTION OUTPUT TRISTATE ;
    USE SIGNAL ;
    PORT
      LAYER met2 ;
        RECT 526.790 0.000 527.070 4.000 ;
    END
  END X_imag[7]
  PIN X_imag[80]
    DIRECTION OUTPUT TRISTATE ;
    USE SIGNAL ;
    PORT
      LAYER met2 ;
        RECT 253.090 0.000 253.370 4.000 ;
    END
  END X_imag[80]
  PIN X_imag[81]
    DIRECTION OUTPUT TRISTATE ;
    USE SIGNAL ;
    PORT
      LAYER met3 ;
        RECT 0.000 608.640 4.000 609.240 ;
    END
  END X_imag[81]
  PIN X_imag[82]
    DIRECTION OUTPUT TRISTATE ;
    USE SIGNAL ;
    PORT
      LAYER met3 ;
        RECT 0.000 516.840 4.000 517.440 ;
    END
  END X_imag[82]
  PIN X_imag[83]
    DIRECTION OUTPUT TRISTATE ;
    USE SIGNAL ;
    PORT
      LAYER met3 ;
        RECT 720.020 30.640 724.020 31.240 ;
    END
  END X_imag[83]
  PIN X_imag[84]
    DIRECTION OUTPUT TRISTATE ;
    USE SIGNAL ;
    PORT
      LAYER met2 ;
        RECT 641.790 730.740 642.070 734.740 ;
    END
  END X_imag[84]
  PIN X_imag[85]
    DIRECTION OUTPUT TRISTATE ;
    USE SIGNAL ;
    PORT
      LAYER met2 ;
        RECT 598.090 730.740 598.370 734.740 ;
    END
  END X_imag[85]
  PIN X_imag[86]
    DIRECTION OUTPUT TRISTATE ;
    USE SIGNAL ;
    PORT
      LAYER met3 ;
        RECT 720.020 285.640 724.020 286.240 ;
    END
  END X_imag[86]
  PIN X_imag[87]
    DIRECTION OUTPUT TRISTATE ;
    USE SIGNAL ;
    PORT
      LAYER met3 ;
        RECT 720.020 357.040 724.020 357.640 ;
    END
  END X_imag[87]
  PIN X_imag[88]
    DIRECTION OUTPUT TRISTATE ;
    USE SIGNAL ;
    PORT
      LAYER met2 ;
        RECT 158.790 730.740 159.070 734.740 ;
    END
  END X_imag[88]
  PIN X_imag[89]
    DIRECTION OUTPUT TRISTATE ;
    USE SIGNAL ;
    PORT
      LAYER met2 ;
        RECT 243.890 0.000 244.170 4.000 ;
    END
  END X_imag[89]
  PIN X_imag[8]
    DIRECTION OUTPUT TRISTATE ;
    USE SIGNAL ;
    PORT
      LAYER met2 ;
        RECT 496.890 0.000 497.170 4.000 ;
    END
  END X_imag[8]
  PIN X_imag[90]
    DIRECTION OUTPUT TRISTATE ;
    USE SIGNAL ;
    PORT
      LAYER met2 ;
        RECT 464.690 0.000 464.970 4.000 ;
    END
  END X_imag[90]
  PIN X_imag[91]
    DIRECTION OUTPUT TRISTATE ;
    USE SIGNAL ;
    PORT
      LAYER met3 ;
        RECT 720.020 598.440 724.020 599.040 ;
    END
  END X_imag[91]
  PIN X_imag[92]
    DIRECTION OUTPUT TRISTATE ;
    USE SIGNAL ;
    PORT
      LAYER met2 ;
        RECT 407.190 730.740 407.470 734.740 ;
    END
  END X_imag[92]
  PIN X_imag[93]
    DIRECTION OUTPUT TRISTATE ;
    USE SIGNAL ;
    PORT
      LAYER met2 ;
        RECT 94.390 0.000 94.670 4.000 ;
    END
  END X_imag[93]
  PIN X_imag[94]
    DIRECTION OUTPUT TRISTATE ;
    USE SIGNAL ;
    PORT
      LAYER met3 ;
        RECT 0.000 176.840 4.000 177.440 ;
    END
  END X_imag[94]
  PIN X_imag[95]
    DIRECTION OUTPUT TRISTATE ;
    USE SIGNAL ;
    PORT
      LAYER met3 ;
        RECT 0.000 387.640 4.000 388.240 ;
    END
  END X_imag[95]
  PIN X_imag[96]
    DIRECTION OUTPUT TRISTATE ;
    USE SIGNAL ;
    PORT
      LAYER met2 ;
        RECT 411.790 730.740 412.070 734.740 ;
    END
  END X_imag[96]
  PIN X_imag[97]
    DIRECTION OUTPUT TRISTATE ;
    USE SIGNAL ;
    PORT
      LAYER met2 ;
        RECT 161.090 0.000 161.370 4.000 ;
    END
  END X_imag[97]
  PIN X_imag[98]
    DIRECTION OUTPUT TRISTATE ;
    USE SIGNAL ;
    PORT
      LAYER met3 ;
        RECT 0.000 173.440 4.000 174.040 ;
    END
  END X_imag[98]
  PIN X_imag[99]
    DIRECTION OUTPUT TRISTATE ;
    USE SIGNAL ;
    PORT
      LAYER met2 ;
        RECT 563.590 0.000 563.870 4.000 ;
    END
  END X_imag[99]
  PIN X_imag[9]
    DIRECTION OUTPUT TRISTATE ;
    USE SIGNAL ;
    PORT
      LAYER met2 ;
        RECT 66.790 730.740 67.070 734.740 ;
    END
  END X_imag[9]
  PIN X_real[0]
    DIRECTION OUTPUT TRISTATE ;
    USE SIGNAL ;
    PORT
      LAYER met3 ;
        RECT 720.020 448.840 724.020 449.440 ;
    END
  END X_real[0]
  PIN X_real[100]
    DIRECTION OUTPUT TRISTATE ;
    USE SIGNAL ;
    PORT
      LAYER met3 ;
        RECT 0.000 472.640 4.000 473.240 ;
    END
  END X_real[100]
  PIN X_real[101]
    DIRECTION OUTPUT TRISTATE ;
    USE SIGNAL ;
    PORT
      LAYER met3 ;
        RECT 0.000 663.040 4.000 663.640 ;
    END
  END X_real[101]
  PIN X_real[102]
    DIRECTION OUTPUT TRISTATE ;
    USE SIGNAL ;
    PORT
      LAYER met3 ;
        RECT 720.020 139.440 724.020 140.040 ;
    END
  END X_real[102]
  PIN X_real[103]
    DIRECTION OUTPUT TRISTATE ;
    USE SIGNAL ;
    PORT
      LAYER met2 ;
        RECT 322.090 730.740 322.370 734.740 ;
    END
  END X_real[103]
  PIN X_real[104]
    DIRECTION OUTPUT TRISTATE ;
    USE SIGNAL ;
    PORT
      LAYER met2 ;
        RECT 515.290 0.000 515.570 4.000 ;
    END
  END X_real[104]
  PIN X_real[105]
    DIRECTION OUTPUT TRISTATE ;
    USE SIGNAL ;
    PORT
      LAYER met3 ;
        RECT 0.000 720.840 4.000 721.440 ;
    END
  END X_real[105]
  PIN X_real[106]
    DIRECTION OUTPUT TRISTATE ;
    USE SIGNAL ;
    PORT
      LAYER met2 ;
        RECT 478.490 0.000 478.770 4.000 ;
    END
  END X_real[106]
  PIN X_real[107]
    DIRECTION OUTPUT TRISTATE ;
    USE SIGNAL ;
    PORT
      LAYER met3 ;
        RECT 0.000 210.840 4.000 211.440 ;
    END
  END X_real[107]
  PIN X_real[108]
    DIRECTION OUTPUT TRISTATE ;
    USE SIGNAL ;
    PORT
      LAYER met2 ;
        RECT 133.490 0.000 133.770 4.000 ;
    END
  END X_real[108]
  PIN X_real[109]
    DIRECTION OUTPUT TRISTATE ;
    USE SIGNAL ;
    PORT
      LAYER met2 ;
        RECT 96.690 730.740 96.970 734.740 ;
    END
  END X_real[109]
  PIN X_real[10]
    DIRECTION OUTPUT TRISTATE ;
    USE SIGNAL ;
    PORT
      LAYER met2 ;
        RECT 296.790 730.740 297.070 734.740 ;
    END
  END X_real[10]
  PIN X_real[110]
    DIRECTION OUTPUT TRISTATE ;
    USE SIGNAL ;
    PORT
      LAYER met2 ;
        RECT 572.790 0.000 573.070 4.000 ;
    END
  END X_real[110]
  PIN X_real[111]
    DIRECTION OUTPUT TRISTATE ;
    USE SIGNAL ;
    PORT
      LAYER met2 ;
        RECT 75.990 0.000 76.270 4.000 ;
    END
  END X_real[111]
  PIN X_real[112]
    DIRECTION OUTPUT TRISTATE ;
    USE SIGNAL ;
    PORT
      LAYER met2 ;
        RECT 301.390 730.740 301.670 734.740 ;
    END
  END X_real[112]
  PIN X_real[113]
    DIRECTION OUTPUT TRISTATE ;
    USE SIGNAL ;
    PORT
      LAYER met3 ;
        RECT 720.020 697.040 724.020 697.640 ;
    END
  END X_real[113]
  PIN X_real[114]
    DIRECTION OUTPUT TRISTATE ;
    USE SIGNAL ;
    PORT
      LAYER met2 ;
        RECT 565.890 730.740 566.170 734.740 ;
    END
  END X_real[114]
  PIN X_real[115]
    DIRECTION OUTPUT TRISTATE ;
    USE SIGNAL ;
    PORT
      LAYER met2 ;
        RECT 637.190 730.740 637.470 734.740 ;
    END
  END X_real[115]
  PIN X_real[116]
    DIRECTION OUTPUT TRISTATE ;
    USE SIGNAL ;
    PORT
      LAYER met3 ;
        RECT 0.000 479.440 4.000 480.040 ;
    END
  END X_real[116]
  PIN X_real[117]
    DIRECTION OUTPUT TRISTATE ;
    USE SIGNAL ;
    PORT
      LAYER met2 ;
        RECT 225.490 730.740 225.770 734.740 ;
    END
  END X_real[117]
  PIN X_real[118]
    DIRECTION OUTPUT TRISTATE ;
    USE SIGNAL ;
    PORT
      LAYER met2 ;
        RECT 209.390 0.000 209.670 4.000 ;
    END
  END X_real[118]
  PIN X_real[119]
    DIRECTION OUTPUT TRISTATE ;
    USE SIGNAL ;
    PORT
      LAYER met3 ;
        RECT 0.000 197.240 4.000 197.840 ;
    END
  END X_real[119]
  PIN X_real[11]
    DIRECTION OUTPUT TRISTATE ;
    USE SIGNAL ;
    PORT
      LAYER met3 ;
        RECT 720.020 540.640 724.020 541.240 ;
    END
  END X_real[11]
  PIN X_real[120]
    DIRECTION OUTPUT TRISTATE ;
    USE SIGNAL ;
    PORT
      LAYER met2 ;
        RECT 618.790 730.740 619.070 734.740 ;
    END
  END X_real[120]
  PIN X_real[121]
    DIRECTION OUTPUT TRISTATE ;
    USE SIGNAL ;
    PORT
      LAYER met3 ;
        RECT 0.000 727.640 4.000 728.240 ;
    END
  END X_real[121]
  PIN X_real[122]
    DIRECTION OUTPUT TRISTATE ;
    USE SIGNAL ;
    PORT
      LAYER met3 ;
        RECT 0.000 642.640 4.000 643.240 ;
    END
  END X_real[122]
  PIN X_real[123]
    DIRECTION OUTPUT TRISTATE ;
    USE SIGNAL ;
    PORT
      LAYER met3 ;
        RECT 0.000 27.240 4.000 27.840 ;
    END
  END X_real[123]
  PIN X_real[124]
    DIRECTION OUTPUT TRISTATE ;
    USE SIGNAL ;
    PORT
      LAYER met2 ;
        RECT 434.790 0.000 435.070 4.000 ;
    END
  END X_real[124]
  PIN X_real[125]
    DIRECTION OUTPUT TRISTATE ;
    USE SIGNAL ;
    PORT
      LAYER met2 ;
        RECT 62.190 730.740 62.470 734.740 ;
    END
  END X_real[125]
  PIN X_real[126]
    DIRECTION OUTPUT TRISTATE ;
    USE SIGNAL ;
    PORT
      LAYER met2 ;
        RECT 478.490 730.740 478.770 734.740 ;
    END
  END X_real[126]
  PIN X_real[127]
    DIRECTION OUTPUT TRISTATE ;
    USE SIGNAL ;
    PORT
      LAYER met2 ;
        RECT 545.190 0.000 545.470 4.000 ;
    END
  END X_real[127]
  PIN X_real[128]
    DIRECTION OUTPUT TRISTATE ;
    USE SIGNAL ;
    PORT
      LAYER met2 ;
        RECT 213.990 0.000 214.270 4.000 ;
    END
  END X_real[128]
  PIN X_real[129]
    DIRECTION OUTPUT TRISTATE ;
    USE SIGNAL ;
    PORT
      LAYER met2 ;
        RECT 101.290 730.740 101.570 734.740 ;
    END
  END X_real[129]
  PIN X_real[12]
    DIRECTION OUTPUT TRISTATE ;
    USE SIGNAL ;
    PORT
      LAYER met3 ;
        RECT 0.000 601.840 4.000 602.440 ;
    END
  END X_real[12]
  PIN X_real[130]
    DIRECTION OUTPUT TRISTATE ;
    USE SIGNAL ;
    PORT
      LAYER met2 ;
        RECT 269.190 730.740 269.470 734.740 ;
    END
  END X_real[130]
  PIN X_real[131]
    DIRECTION OUTPUT TRISTATE ;
    USE SIGNAL ;
    PORT
      LAYER met3 ;
        RECT 0.000 231.240 4.000 231.840 ;
    END
  END X_real[131]
  PIN X_real[132]
    DIRECTION OUTPUT TRISTATE ;
    USE SIGNAL ;
    PORT
      LAYER met3 ;
        RECT 720.020 54.440 724.020 55.040 ;
    END
  END X_real[132]
  PIN X_real[133]
    DIRECTION OUTPUT TRISTATE ;
    USE SIGNAL ;
    PORT
      LAYER met2 ;
        RECT 713.090 730.740 713.370 734.740 ;
    END
  END X_real[133]
  PIN X_real[134]
    DIRECTION OUTPUT TRISTATE ;
    USE SIGNAL ;
    PORT
      LAYER met2 ;
        RECT 257.690 0.000 257.970 4.000 ;
    END
  END X_real[134]
  PIN X_real[135]
    DIRECTION OUTPUT TRISTATE ;
    USE SIGNAL ;
    PORT
      LAYER met3 ;
        RECT 720.020 187.040 724.020 187.640 ;
    END
  END X_real[135]
  PIN X_real[136]
    DIRECTION OUTPUT TRISTATE ;
    USE SIGNAL ;
    PORT
      LAYER met2 ;
        RECT 108.190 0.000 108.470 4.000 ;
    END
  END X_real[136]
  PIN X_real[137]
    DIRECTION OUTPUT TRISTATE ;
    USE SIGNAL ;
    PORT
      LAYER met3 ;
        RECT 0.000 166.640 4.000 167.240 ;
    END
  END X_real[137]
  PIN X_real[138]
    DIRECTION OUTPUT TRISTATE ;
    USE SIGNAL ;
    PORT
      LAYER met3 ;
        RECT 0.000 414.840 4.000 415.440 ;
    END
  END X_real[138]
  PIN X_real[139]
    DIRECTION OUTPUT TRISTATE ;
    USE SIGNAL ;
    PORT
      LAYER met3 ;
        RECT 720.020 472.640 724.020 473.240 ;
    END
  END X_real[139]
  PIN X_real[13]
    DIRECTION OUTPUT TRISTATE ;
    USE SIGNAL ;
    PORT
      LAYER met2 ;
        RECT 232.390 0.000 232.670 4.000 ;
    END
  END X_real[13]
  PIN X_real[140]
    DIRECTION OUTPUT TRISTATE ;
    USE SIGNAL ;
    PORT
      LAYER met2 ;
        RECT 328.990 0.000 329.270 4.000 ;
    END
  END X_real[140]
  PIN X_real[141]
    DIRECTION OUTPUT TRISTATE ;
    USE SIGNAL ;
    PORT
      LAYER met3 ;
        RECT 720.020 435.240 724.020 435.840 ;
    END
  END X_real[141]
  PIN X_real[142]
    DIRECTION OUTPUT TRISTATE ;
    USE SIGNAL ;
    PORT
      LAYER met2 ;
        RECT 425.590 730.740 425.870 734.740 ;
    END
  END X_real[142]
  PIN X_real[143]
    DIRECTION OUTPUT TRISTATE ;
    USE SIGNAL ;
    PORT
      LAYER met2 ;
        RECT 142.690 730.740 142.970 734.740 ;
    END
  END X_real[143]
  PIN X_real[144]
    DIRECTION OUTPUT TRISTATE ;
    USE SIGNAL ;
    PORT
      LAYER met3 ;
        RECT 0.000 13.640 4.000 14.240 ;
    END
  END X_real[144]
  PIN X_real[145]
    DIRECTION OUTPUT TRISTATE ;
    USE SIGNAL ;
    PORT
      LAYER met2 ;
        RECT 443.990 0.000 444.270 4.000 ;
    END
  END X_real[145]
  PIN X_real[146]
    DIRECTION OUTPUT TRISTATE ;
    USE SIGNAL ;
    PORT
      LAYER met3 ;
        RECT 0.000 693.640 4.000 694.240 ;
    END
  END X_real[146]
  PIN X_real[147]
    DIRECTION OUTPUT TRISTATE ;
    USE SIGNAL ;
    PORT
      LAYER met2 ;
        RECT 416.390 0.000 416.670 4.000 ;
    END
  END X_real[147]
  PIN X_real[148]
    DIRECTION OUTPUT TRISTATE ;
    USE SIGNAL ;
    PORT
      LAYER met3 ;
        RECT 720.020 292.440 724.020 293.040 ;
    END
  END X_real[148]
  PIN X_real[149]
    DIRECTION OUTPUT TRISTATE ;
    USE SIGNAL ;
    PORT
      LAYER met2 ;
        RECT 577.390 0.000 577.670 4.000 ;
    END
  END X_real[149]
  PIN X_real[14]
    DIRECTION OUTPUT TRISTATE ;
    USE SIGNAL ;
    PORT
      LAYER met2 ;
        RECT 315.190 730.740 315.470 734.740 ;
    END
  END X_real[14]
  PIN X_real[150]
    DIRECTION OUTPUT TRISTATE ;
    USE SIGNAL ;
    PORT
      LAYER met3 ;
        RECT 720.020 421.640 724.020 422.240 ;
    END
  END X_real[150]
  PIN X_real[151]
    DIRECTION OUTPUT TRISTATE ;
    USE SIGNAL ;
    PORT
      LAYER met2 ;
        RECT 374.990 730.740 375.270 734.740 ;
    END
  END X_real[151]
  PIN X_real[152]
    DIRECTION OUTPUT TRISTATE ;
    USE SIGNAL ;
    PORT
      LAYER met3 ;
        RECT 720.020 408.040 724.020 408.640 ;
    END
  END X_real[152]
  PIN X_real[153]
    DIRECTION OUTPUT TRISTATE ;
    USE SIGNAL ;
    PORT
      LAYER met2 ;
        RECT 646.390 730.740 646.670 734.740 ;
    END
  END X_real[153]
  PIN X_real[154]
    DIRECTION OUTPUT TRISTATE ;
    USE SIGNAL ;
    PORT
      LAYER met2 ;
        RECT 699.290 730.740 699.570 734.740 ;
    END
  END X_real[154]
  PIN X_real[155]
    DIRECTION OUTPUT TRISTATE ;
    USE SIGNAL ;
    PORT
      LAYER met2 ;
        RECT 420.990 0.000 421.270 4.000 ;
    END
  END X_real[155]
  PIN X_real[156]
    DIRECTION OUTPUT TRISTATE ;
    USE SIGNAL ;
    PORT
      LAYER met2 ;
        RECT 487.690 730.740 487.970 734.740 ;
    END
  END X_real[156]
  PIN X_real[157]
    DIRECTION OUTPUT TRISTATE ;
    USE SIGNAL ;
    PORT
      LAYER met3 ;
        RECT 0.000 153.040 4.000 153.640 ;
    END
  END X_real[157]
  PIN X_real[158]
    DIRECTION OUTPUT TRISTATE ;
    USE SIGNAL ;
    PORT
      LAYER met2 ;
        RECT 703.890 0.000 704.170 4.000 ;
    END
  END X_real[158]
  PIN X_real[159]
    DIRECTION OUTPUT TRISTATE ;
    USE SIGNAL ;
    PORT
      LAYER met3 ;
        RECT 720.020 401.240 724.020 401.840 ;
    END
  END X_real[159]
  PIN X_real[15]
    DIRECTION OUTPUT TRISTATE ;
    USE SIGNAL ;
    PORT
      LAYER met2 ;
        RECT 381.890 0.000 382.170 4.000 ;
    END
  END X_real[15]
  PIN X_real[160]
    DIRECTION OUTPUT TRISTATE ;
    USE SIGNAL ;
    PORT
      LAYER met3 ;
        RECT 0.000 329.840 4.000 330.440 ;
    END
  END X_real[160]
  PIN X_real[161]
    DIRECTION OUTPUT TRISTATE ;
    USE SIGNAL ;
    PORT
      LAYER met2 ;
        RECT 39.190 730.740 39.470 734.740 ;
    END
  END X_real[161]
  PIN X_real[162]
    DIRECTION OUTPUT TRISTATE ;
    USE SIGNAL ;
    PORT
      LAYER met2 ;
        RECT 338.190 0.000 338.470 4.000 ;
    END
  END X_real[162]
  PIN X_real[163]
    DIRECTION OUTPUT TRISTATE ;
    USE SIGNAL ;
    PORT
      LAYER met3 ;
        RECT 720.020 527.040 724.020 527.640 ;
    END
  END X_real[163]
  PIN X_real[164]
    DIRECTION OUTPUT TRISTATE ;
    USE SIGNAL ;
    PORT
      LAYER met3 ;
        RECT 720.020 683.440 724.020 684.040 ;
    END
  END X_real[164]
  PIN X_real[165]
    DIRECTION OUTPUT TRISTATE ;
    USE SIGNAL ;
    PORT
      LAYER met3 ;
        RECT 0.000 88.440 4.000 89.040 ;
    END
  END X_real[165]
  PIN X_real[166]
    DIRECTION OUTPUT TRISTATE ;
    USE SIGNAL ;
    PORT
      LAYER met3 ;
        RECT 720.020 520.240 724.020 520.840 ;
    END
  END X_real[166]
  PIN X_real[167]
    DIRECTION OUTPUT TRISTATE ;
    USE SIGNAL ;
    PORT
      LAYER met2 ;
        RECT 319.790 0.000 320.070 4.000 ;
    END
  END X_real[167]
  PIN X_real[168]
    DIRECTION OUTPUT TRISTATE ;
    USE SIGNAL ;
    PORT
      LAYER met2 ;
        RECT 177.190 730.740 177.470 734.740 ;
    END
  END X_real[168]
  PIN X_real[169]
    DIRECTION OUTPUT TRISTATE ;
    USE SIGNAL ;
    PORT
      LAYER met3 ;
        RECT 0.000 676.640 4.000 677.240 ;
    END
  END X_real[169]
  PIN X_real[16]
    DIRECTION OUTPUT TRISTATE ;
    USE SIGNAL ;
    PORT
      LAYER met3 ;
        RECT 720.020 173.440 724.020 174.040 ;
    END
  END X_real[16]
  PIN X_real[170]
    DIRECTION OUTPUT TRISTATE ;
    USE SIGNAL ;
    PORT
      LAYER met3 ;
        RECT 720.020 146.240 724.020 146.840 ;
    END
  END X_real[170]
  PIN X_real[171]
    DIRECTION OUTPUT TRISTATE ;
    USE SIGNAL ;
    PORT
      LAYER met3 ;
        RECT 720.020 554.240 724.020 554.840 ;
    END
  END X_real[171]
  PIN X_real[172]
    DIRECTION OUTPUT TRISTATE ;
    USE SIGNAL ;
    PORT
      LAYER met3 ;
        RECT 0.000 544.040 4.000 544.640 ;
    END
  END X_real[172]
  PIN X_real[173]
    DIRECTION OUTPUT TRISTATE ;
    USE SIGNAL ;
    PORT
      LAYER met3 ;
        RECT 720.020 428.440 724.020 429.040 ;
    END
  END X_real[173]
  PIN X_real[174]
    DIRECTION OUTPUT TRISTATE ;
    USE SIGNAL ;
    PORT
      LAYER met3 ;
        RECT 720.020 350.240 724.020 350.840 ;
    END
  END X_real[174]
  PIN X_real[175]
    DIRECTION OUTPUT TRISTATE ;
    USE SIGNAL ;
    PORT
      LAYER met2 ;
        RECT 692.390 0.000 692.670 4.000 ;
    END
  END X_real[175]
  PIN X_real[176]
    DIRECTION OUTPUT TRISTATE ;
    USE SIGNAL ;
    PORT
      LAYER met3 ;
        RECT 720.020 207.440 724.020 208.040 ;
    END
  END X_real[176]
  PIN X_real[177]
    DIRECTION OUTPUT TRISTATE ;
    USE SIGNAL ;
    PORT
      LAYER met3 ;
        RECT 720.020 414.840 724.020 415.440 ;
    END
  END X_real[177]
  PIN X_real[178]
    DIRECTION OUTPUT TRISTATE ;
    USE SIGNAL ;
    PORT
      LAYER met2 ;
        RECT 637.190 0.000 637.470 4.000 ;
    END
  END X_real[178]
  PIN X_real[179]
    DIRECTION OUTPUT TRISTATE ;
    USE SIGNAL ;
    PORT
      LAYER met2 ;
        RECT 333.590 0.000 333.870 4.000 ;
    END
  END X_real[179]
  PIN X_real[17]
    DIRECTION OUTPUT TRISTATE ;
    USE SIGNAL ;
    PORT
      LAYER met2 ;
        RECT 432.490 730.740 432.770 734.740 ;
    END
  END X_real[17]
  PIN X_real[180]
    DIRECTION OUTPUT TRISTATE ;
    USE SIGNAL ;
    PORT
      LAYER met3 ;
        RECT 0.000 700.440 4.000 701.040 ;
    END
  END X_real[180]
  PIN X_real[181]
    DIRECTION OUTPUT TRISTATE ;
    USE SIGNAL ;
    PORT
      LAYER met2 ;
        RECT 545.190 730.740 545.470 734.740 ;
    END
  END X_real[181]
  PIN X_real[182]
    DIRECTION OUTPUT TRISTATE ;
    USE SIGNAL ;
    PORT
      LAYER met2 ;
        RECT 547.490 730.740 547.770 734.740 ;
    END
  END X_real[182]
  PIN X_real[183]
    DIRECTION OUTPUT TRISTATE ;
    USE SIGNAL ;
    PORT
      LAYER met2 ;
        RECT 457.790 0.000 458.070 4.000 ;
    END
  END X_real[183]
  PIN X_real[184]
    DIRECTION OUTPUT TRISTATE ;
    USE SIGNAL ;
    PORT
      LAYER met2 ;
        RECT 262.290 0.000 262.570 4.000 ;
    END
  END X_real[184]
  PIN X_real[185]
    DIRECTION OUTPUT TRISTATE ;
    USE SIGNAL ;
    PORT
      LAYER met3 ;
        RECT 0.000 686.840 4.000 687.440 ;
    END
  END X_real[185]
  PIN X_real[186]
    DIRECTION OUTPUT TRISTATE ;
    USE SIGNAL ;
    PORT
      LAYER met3 ;
        RECT 0.000 346.840 4.000 347.440 ;
    END
  END X_real[186]
  PIN X_real[187]
    DIRECTION OUTPUT TRISTATE ;
    USE SIGNAL ;
    PORT
      LAYER met2 ;
        RECT 331.290 730.740 331.570 734.740 ;
    END
  END X_real[187]
  PIN X_real[188]
    DIRECTION OUTPUT TRISTATE ;
    USE SIGNAL ;
    PORT
      LAYER met3 ;
        RECT 720.020 533.840 724.020 534.440 ;
    END
  END X_real[188]
  PIN X_real[189]
    DIRECTION OUTPUT TRISTATE ;
    USE SIGNAL ;
    PORT
      LAYER met3 ;
        RECT 720.020 336.640 724.020 337.240 ;
    END
  END X_real[189]
  PIN X_real[18]
    DIRECTION OUTPUT TRISTATE ;
    USE SIGNAL ;
    PORT
      LAYER met2 ;
        RECT 151.890 0.000 152.170 4.000 ;
    END
  END X_real[18]
  PIN X_real[190]
    DIRECTION OUTPUT TRISTATE ;
    USE SIGNAL ;
    PORT
      LAYER met3 ;
        RECT 720.020 642.640 724.020 643.240 ;
    END
  END X_real[190]
  PIN X_real[191]
    DIRECTION OUTPUT TRISTATE ;
    USE SIGNAL ;
    PORT
      LAYER met2 ;
        RECT 349.690 0.000 349.970 4.000 ;
    END
  END X_real[191]
  PIN X_real[192]
    DIRECTION OUTPUT TRISTATE ;
    USE SIGNAL ;
    PORT
      LAYER met3 ;
        RECT 720.020 214.240 724.020 214.840 ;
    END
  END X_real[192]
  PIN X_real[193]
    DIRECTION OUTPUT TRISTATE ;
    USE SIGNAL ;
    PORT
      LAYER met3 ;
        RECT 720.020 258.440 724.020 259.040 ;
    END
  END X_real[193]
  PIN X_real[194]
    DIRECTION OUTPUT TRISTATE ;
    USE SIGNAL ;
    PORT
      LAYER met2 ;
        RECT 195.590 0.000 195.870 4.000 ;
    END
  END X_real[194]
  PIN X_real[195]
    DIRECTION OUTPUT TRISTATE ;
    USE SIGNAL ;
    PORT
      LAYER met2 ;
        RECT 154.190 730.740 154.470 734.740 ;
    END
  END X_real[195]
  PIN X_real[196]
    DIRECTION OUTPUT TRISTATE ;
    USE SIGNAL ;
    PORT
      LAYER met2 ;
        RECT 453.190 0.000 453.470 4.000 ;
    END
  END X_real[196]
  PIN X_real[197]
    DIRECTION OUTPUT TRISTATE ;
    USE SIGNAL ;
    PORT
      LAYER met3 ;
        RECT 720.020 316.240 724.020 316.840 ;
    END
  END X_real[197]
  PIN X_real[198]
    DIRECTION OUTPUT TRISTATE ;
    USE SIGNAL ;
    PORT
      LAYER met3 ;
        RECT 0.000 146.240 4.000 146.840 ;
    END
  END X_real[198]
  PIN X_real[199]
    DIRECTION OUTPUT TRISTATE ;
    USE SIGNAL ;
    PORT
      LAYER met2 ;
        RECT 271.490 0.000 271.770 4.000 ;
    END
  END X_real[199]
  PIN X_real[19]
    DIRECTION OUTPUT TRISTATE ;
    USE SIGNAL ;
    PORT
      LAYER met3 ;
        RECT 0.000 629.040 4.000 629.640 ;
    END
  END X_real[19]
  PIN X_real[1]
    DIRECTION OUTPUT TRISTATE ;
    USE SIGNAL ;
    PORT
      LAYER met2 ;
        RECT 404.890 0.000 405.170 4.000 ;
    END
  END X_real[1]
  PIN X_real[200]
    DIRECTION OUTPUT TRISTATE ;
    USE SIGNAL ;
    PORT
      LAYER met2 ;
        RECT 522.190 730.740 522.470 734.740 ;
    END
  END X_real[200]
  PIN X_real[201]
    DIRECTION OUTPUT TRISTATE ;
    USE SIGNAL ;
    PORT
      LAYER met2 ;
        RECT 441.690 730.740 441.970 734.740 ;
    END
  END X_real[201]
  PIN X_real[202]
    DIRECTION OUTPUT TRISTATE ;
    USE SIGNAL ;
    PORT
      LAYER met2 ;
        RECT 147.290 0.000 147.570 4.000 ;
    END
  END X_real[202]
  PIN X_real[203]
    DIRECTION OUTPUT TRISTATE ;
    USE SIGNAL ;
    PORT
      LAYER met2 ;
        RECT 687.790 0.000 688.070 4.000 ;
    END
  END X_real[203]
  PIN X_real[204]
    DIRECTION OUTPUT TRISTATE ;
    USE SIGNAL ;
    PORT
      LAYER met2 ;
        RECT 623.390 730.740 623.670 734.740 ;
    END
  END X_real[204]
  PIN X_real[205]
    DIRECTION OUTPUT TRISTATE ;
    USE SIGNAL ;
    PORT
      LAYER met3 ;
        RECT 0.000 550.840 4.000 551.440 ;
    END
  END X_real[205]
  PIN X_real[206]
    DIRECTION OUTPUT TRISTATE ;
    USE SIGNAL ;
    PORT
      LAYER met2 ;
        RECT 400.290 0.000 400.570 4.000 ;
    END
  END X_real[206]
  PIN X_real[207]
    DIRECTION OUTPUT TRISTATE ;
    USE SIGNAL ;
    PORT
      LAYER met2 ;
        RECT 579.690 730.740 579.970 734.740 ;
    END
  END X_real[207]
  PIN X_real[208]
    DIRECTION OUTPUT TRISTATE ;
    USE SIGNAL ;
    PORT
      LAYER met2 ;
        RECT 719.990 730.740 720.270 734.740 ;
    END
  END X_real[208]
  PIN X_real[209]
    DIRECTION OUTPUT TRISTATE ;
    USE SIGNAL ;
    PORT
      LAYER met2 ;
        RECT 519.890 0.000 520.170 4.000 ;
    END
  END X_real[209]
  PIN X_real[20]
    DIRECTION OUTPUT TRISTATE ;
    USE SIGNAL ;
    PORT
      LAYER met2 ;
        RECT 92.090 730.740 92.370 734.740 ;
    END
  END X_real[20]
  PIN X_real[210]
    DIRECTION OUTPUT TRISTATE ;
    USE SIGNAL ;
    PORT
      LAYER met2 ;
        RECT 190.990 0.000 191.270 4.000 ;
    END
  END X_real[210]
  PIN X_real[211]
    DIRECTION OUTPUT TRISTATE ;
    USE SIGNAL ;
    PORT
      LAYER met3 ;
        RECT 0.000 244.840 4.000 245.440 ;
    END
  END X_real[211]
  PIN X_real[212]
    DIRECTION OUTPUT TRISTATE ;
    USE SIGNAL ;
    PORT
      LAYER met2 ;
        RECT 138.090 0.000 138.370 4.000 ;
    END
  END X_real[212]
  PIN X_real[213]
    DIRECTION OUTPUT TRISTATE ;
    USE SIGNAL ;
    PORT
      LAYER met2 ;
        RECT 492.290 0.000 492.570 4.000 ;
    END
  END X_real[213]
  PIN X_real[214]
    DIRECTION OUTPUT TRISTATE ;
    USE SIGNAL ;
    PORT
      LAYER met3 ;
        RECT 0.000 61.240 4.000 61.840 ;
    END
  END X_real[214]
  PIN X_real[215]
    DIRECTION OUTPUT TRISTATE ;
    USE SIGNAL ;
    PORT
      LAYER met3 ;
        RECT 720.020 493.040 724.020 493.640 ;
    END
  END X_real[215]
  PIN X_real[216]
    DIRECTION OUTPUT TRISTATE ;
    USE SIGNAL ;
    PORT
      LAYER met2 ;
        RECT 717.690 0.000 717.970 4.000 ;
    END
  END X_real[216]
  PIN X_real[217]
    DIRECTION OUTPUT TRISTATE ;
    USE SIGNAL ;
    PORT
      LAYER met3 ;
        RECT 0.000 268.640 4.000 269.240 ;
    END
  END X_real[217]
  PIN X_real[218]
    DIRECTION OUTPUT TRISTATE ;
    USE SIGNAL ;
    PORT
      LAYER met2 ;
        RECT 372.690 0.000 372.970 4.000 ;
    END
  END X_real[218]
  PIN X_real[219]
    DIRECTION OUTPUT TRISTATE ;
    USE SIGNAL ;
    PORT
      LAYER met3 ;
        RECT 0.000 445.440 4.000 446.040 ;
    END
  END X_real[219]
  PIN X_real[21]
    DIRECTION OUTPUT TRISTATE ;
    USE SIGNAL ;
    PORT
      LAYER met2 ;
        RECT 317.490 730.740 317.770 734.740 ;
    END
  END X_real[21]
  PIN X_real[220]
    DIRECTION OUTPUT TRISTATE ;
    USE SIGNAL ;
    PORT
      LAYER met2 ;
        RECT 195.590 730.740 195.870 734.740 ;
    END
  END X_real[220]
  PIN X_real[221]
    DIRECTION OUTPUT TRISTATE ;
    USE SIGNAL ;
    PORT
      LAYER met2 ;
        RECT 55.290 0.000 55.570 4.000 ;
    END
  END X_real[221]
  PIN X_real[222]
    DIRECTION OUTPUT TRISTATE ;
    USE SIGNAL ;
    PORT
      LAYER met2 ;
        RECT 575.090 730.740 575.370 734.740 ;
    END
  END X_real[222]
  PIN X_real[223]
    DIRECTION OUTPUT TRISTATE ;
    USE SIGNAL ;
    PORT
      LAYER met3 ;
        RECT 0.000 669.840 4.000 670.440 ;
    END
  END X_real[223]
  PIN X_real[224]
    DIRECTION OUTPUT TRISTATE ;
    USE SIGNAL ;
    PORT
      LAYER met2 ;
        RECT 177.190 0.000 177.470 4.000 ;
    END
  END X_real[224]
  PIN X_real[225]
    DIRECTION OUTPUT TRISTATE ;
    USE SIGNAL ;
    PORT
      LAYER met3 ;
        RECT 720.020 690.240 724.020 690.840 ;
    END
  END X_real[225]
  PIN X_real[226]
    DIRECTION OUTPUT TRISTATE ;
    USE SIGNAL ;
    PORT
      LAYER met3 ;
        RECT 720.020 132.640 724.020 133.240 ;
    END
  END X_real[226]
  PIN X_real[227]
    DIRECTION OUTPUT TRISTATE ;
    USE SIGNAL ;
    PORT
      LAYER met2 ;
        RECT 713.090 0.000 713.370 4.000 ;
    END
  END X_real[227]
  PIN X_real[228]
    DIRECTION OUTPUT TRISTATE ;
    USE SIGNAL ;
    PORT
      LAYER met3 ;
        RECT 0.000 714.040 4.000 714.640 ;
    END
  END X_real[228]
  PIN X_real[229]
    DIRECTION OUTPUT TRISTATE ;
    USE SIGNAL ;
    PORT
      LAYER met2 ;
        RECT 627.990 730.740 628.270 734.740 ;
    END
  END X_real[229]
  PIN X_real[22]
    DIRECTION OUTPUT TRISTATE ;
    USE SIGNAL ;
    PORT
      LAYER met2 ;
        RECT 117.390 0.000 117.670 4.000 ;
    END
  END X_real[22]
  PIN X_real[230]
    DIRECTION OUTPUT TRISTATE ;
    USE SIGNAL ;
    PORT
      LAYER met3 ;
        RECT 0.000 578.040 4.000 578.640 ;
    END
  END X_real[230]
  PIN X_real[231]
    DIRECTION OUTPUT TRISTATE ;
    USE SIGNAL ;
    PORT
      LAYER met2 ;
        RECT 397.990 730.740 398.270 734.740 ;
    END
  END X_real[231]
  PIN X_real[232]
    DIRECTION OUTPUT TRISTATE ;
    USE SIGNAL ;
    PORT
      LAYER met2 ;
        RECT 71.390 730.740 71.670 734.740 ;
    END
  END X_real[232]
  PIN X_real[233]
    DIRECTION OUTPUT TRISTATE ;
    USE SIGNAL ;
    PORT
      LAYER met2 ;
        RECT 650.990 0.000 651.270 4.000 ;
    END
  END X_real[233]
  PIN X_real[234]
    DIRECTION OUTPUT TRISTATE ;
    USE SIGNAL ;
    PORT
      LAYER met2 ;
        RECT 462.390 0.000 462.670 4.000 ;
    END
  END X_real[234]
  PIN X_real[235]
    DIRECTION OUTPUT TRISTATE ;
    USE SIGNAL ;
    PORT
      LAYER met2 ;
        RECT 315.190 0.000 315.470 4.000 ;
    END
  END X_real[235]
  PIN X_real[236]
    DIRECTION OUTPUT TRISTATE ;
    USE SIGNAL ;
    PORT
      LAYER met2 ;
        RECT 167.990 730.740 168.270 734.740 ;
    END
  END X_real[236]
  PIN X_real[237]
    DIRECTION OUTPUT TRISTATE ;
    USE SIGNAL ;
    PORT
      LAYER met3 ;
        RECT 720.020 329.840 724.020 330.440 ;
    END
  END X_real[237]
  PIN X_real[238]
    DIRECTION OUTPUT TRISTATE ;
    USE SIGNAL ;
    PORT
      LAYER met3 ;
        RECT 0.000 20.440 4.000 21.040 ;
    END
  END X_real[238]
  PIN X_real[239]
    DIRECTION OUTPUT TRISTATE ;
    USE SIGNAL ;
    PORT
      LAYER met2 ;
        RECT 13.890 730.740 14.170 734.740 ;
    END
  END X_real[239]
  PIN X_real[23]
    DIRECTION OUTPUT TRISTATE ;
    USE SIGNAL ;
    PORT
      LAYER met2 ;
        RECT 287.590 730.740 287.870 734.740 ;
    END
  END X_real[23]
  PIN X_real[240]
    DIRECTION OUTPUT TRISTATE ;
    USE SIGNAL ;
    PORT
      LAYER met3 ;
        RECT 0.000 217.640 4.000 218.240 ;
    END
  END X_real[240]
  PIN X_real[241]
    DIRECTION OUTPUT TRISTATE ;
    USE SIGNAL ;
    PORT
      LAYER met3 ;
        RECT 0.000 289.040 4.000 289.640 ;
    END
  END X_real[241]
  PIN X_real[242]
    DIRECTION OUTPUT TRISTATE ;
    USE SIGNAL ;
    PORT
      LAYER met2 ;
        RECT 561.290 730.740 561.570 734.740 ;
    END
  END X_real[242]
  PIN X_real[243]
    DIRECTION OUTPUT TRISTATE ;
    USE SIGNAL ;
    PORT
      LAYER met2 ;
        RECT 326.690 730.740 326.970 734.740 ;
    END
  END X_real[243]
  PIN X_real[244]
    DIRECTION OUTPUT TRISTATE ;
    USE SIGNAL ;
    PORT
      LAYER met2 ;
        RECT 579.690 0.000 579.970 4.000 ;
    END
  END X_real[244]
  PIN X_real[245]
    DIRECTION OUTPUT TRISTATE ;
    USE SIGNAL ;
    PORT
      LAYER met3 ;
        RECT 0.000 656.240 4.000 656.840 ;
    END
  END X_real[245]
  PIN X_real[246]
    DIRECTION OUTPUT TRISTATE ;
    USE SIGNAL ;
    PORT
      LAYER met2 ;
        RECT 632.590 730.740 632.870 734.740 ;
    END
  END X_real[246]
  PIN X_real[247]
    DIRECTION OUTPUT TRISTATE ;
    USE SIGNAL ;
    PORT
      LAYER met3 ;
        RECT 0.000 486.240 4.000 486.840 ;
    END
  END X_real[247]
  PIN X_real[248]
    DIRECTION OUTPUT TRISTATE ;
    USE SIGNAL ;
    PORT
      LAYER met2 ;
        RECT 446.290 730.740 446.570 734.740 ;
    END
  END X_real[248]
  PIN X_real[249]
    DIRECTION OUTPUT TRISTATE ;
    USE SIGNAL ;
    PORT
      LAYER met2 ;
        RECT 646.390 0.000 646.670 4.000 ;
    END
  END X_real[249]
  PIN X_real[24]
    DIRECTION OUTPUT TRISTATE ;
    USE SIGNAL ;
    PORT
      LAYER met3 ;
        RECT 0.000 499.840 4.000 500.440 ;
    END
  END X_real[24]
  PIN X_real[250]
    DIRECTION OUTPUT TRISTATE ;
    USE SIGNAL ;
    PORT
      LAYER met2 ;
        RECT 292.190 730.740 292.470 734.740 ;
    END
  END X_real[250]
  PIN X_real[251]
    DIRECTION OUTPUT TRISTATE ;
    USE SIGNAL ;
    PORT
      LAYER met2 ;
        RECT 9.290 0.000 9.570 4.000 ;
    END
  END X_real[251]
  PIN X_real[252]
    DIRECTION OUTPUT TRISTATE ;
    USE SIGNAL ;
    PORT
      LAYER met2 ;
        RECT 32.290 0.000 32.570 4.000 ;
    END
  END X_real[252]
  PIN X_real[253]
    DIRECTION OUTPUT TRISTATE ;
    USE SIGNAL ;
    PORT
      LAYER met2 ;
        RECT 377.290 0.000 377.570 4.000 ;
    END
  END X_real[253]
  PIN X_real[254]
    DIRECTION OUTPUT TRISTATE ;
    USE SIGNAL ;
    PORT
      LAYER met2 ;
        RECT 604.990 730.740 605.270 734.740 ;
    END
  END X_real[254]
  PIN X_real[255]
    DIRECTION OUTPUT TRISTATE ;
    USE SIGNAL ;
    PORT
      LAYER met3 ;
        RECT 720.020 499.840 724.020 500.440 ;
    END
  END X_real[255]
  PIN X_real[25]
    DIRECTION OUTPUT TRISTATE ;
    USE SIGNAL ;
    PORT
      LAYER met3 ;
        RECT 720.020 370.640 724.020 371.240 ;
    END
  END X_real[25]
  PIN X_real[26]
    DIRECTION OUTPUT TRISTATE ;
    USE SIGNAL ;
    PORT
      LAYER met2 ;
        RECT 363.490 730.740 363.770 734.740 ;
    END
  END X_real[26]
  PIN X_real[27]
    DIRECTION OUTPUT TRISTATE ;
    USE SIGNAL ;
    PORT
      LAYER met3 ;
        RECT 720.020 469.240 724.020 469.840 ;
    END
  END X_real[27]
  PIN X_real[28]
    DIRECTION OUTPUT TRISTATE ;
    USE SIGNAL ;
    PORT
      LAYER met2 ;
        RECT 230.090 730.740 230.370 734.740 ;
    END
  END X_real[28]
  PIN X_real[29]
    DIRECTION OUTPUT TRISTATE ;
    USE SIGNAL ;
    PORT
      LAYER met3 ;
        RECT 0.000 34.040 4.000 34.640 ;
    END
  END X_real[29]
  PIN X_real[2]
    DIRECTION OUTPUT TRISTATE ;
    USE SIGNAL ;
    PORT
      LAYER met3 ;
        RECT 0.000 421.640 4.000 422.240 ;
    END
  END X_real[2]
  PIN X_real[30]
    DIRECTION OUTPUT TRISTATE ;
    USE SIGNAL ;
    PORT
      LAYER met2 ;
        RECT 372.690 730.740 372.970 734.740 ;
    END
  END X_real[30]
  PIN X_real[31]
    DIRECTION OUTPUT TRISTATE ;
    USE SIGNAL ;
    PORT
      LAYER met2 ;
        RECT 363.490 0.000 363.770 4.000 ;
    END
  END X_real[31]
  PIN X_real[32]
    DIRECTION OUTPUT TRISTATE ;
    USE SIGNAL ;
    PORT
      LAYER met2 ;
        RECT 305.990 730.740 306.270 734.740 ;
    END
  END X_real[32]
  PIN X_real[33]
    DIRECTION OUTPUT TRISTATE ;
    USE SIGNAL ;
    PORT
      LAYER met3 ;
        RECT 0.000 261.840 4.000 262.440 ;
    END
  END X_real[33]
  PIN X_real[34]
    DIRECTION OUTPUT TRISTATE ;
    USE SIGNAL ;
    PORT
      LAYER met2 ;
        RECT 66.790 0.000 67.070 4.000 ;
    END
  END X_real[34]
  PIN X_real[35]
    DIRECTION OUTPUT TRISTATE ;
    USE SIGNAL ;
    PORT
      LAYER met2 ;
        RECT 593.490 0.000 593.770 4.000 ;
    END
  END X_real[35]
  PIN X_real[36]
    DIRECTION OUTPUT TRISTATE ;
    USE SIGNAL ;
    PORT
      LAYER met2 ;
        RECT 186.390 0.000 186.670 4.000 ;
    END
  END X_real[36]
  PIN X_real[37]
    DIRECTION OUTPUT TRISTATE ;
    USE SIGNAL ;
    PORT
      LAYER met2 ;
        RECT 85.190 0.000 85.470 4.000 ;
    END
  END X_real[37]
  PIN X_real[38]
    DIRECTION OUTPUT TRISTATE ;
    USE SIGNAL ;
    PORT
      LAYER met3 ;
        RECT 720.020 724.240 724.020 724.840 ;
    END
  END X_real[38]
  PIN X_real[39]
    DIRECTION OUTPUT TRISTATE ;
    USE SIGNAL ;
    PORT
      LAYER met2 ;
        RECT 301.390 0.000 301.670 4.000 ;
    END
  END X_real[39]
  PIN X_real[3]
    DIRECTION OUTPUT TRISTATE ;
    USE SIGNAL ;
    PORT
      LAYER met3 ;
        RECT 0.000 380.840 4.000 381.440 ;
    END
  END X_real[3]
  PIN X_real[40]
    DIRECTION OUTPUT TRISTATE ;
    USE SIGNAL ;
    PORT
      LAYER met2 ;
        RECT 340.490 730.740 340.770 734.740 ;
    END
  END X_real[40]
  PIN X_real[41]
    DIRECTION OUTPUT TRISTATE ;
    USE SIGNAL ;
    PORT
      LAYER met3 ;
        RECT 720.020 61.240 724.020 61.840 ;
    END
  END X_real[41]
  PIN X_real[42]
    DIRECTION OUTPUT TRISTATE ;
    USE SIGNAL ;
    PORT
      LAYER met2 ;
        RECT 469.290 730.740 469.570 734.740 ;
    END
  END X_real[42]
  PIN X_real[43]
    DIRECTION OUTPUT TRISTATE ;
    USE SIGNAL ;
    PORT
      LAYER met3 ;
        RECT 720.020 377.440 724.020 378.040 ;
    END
  END X_real[43]
  PIN X_real[44]
    DIRECTION OUTPUT TRISTATE ;
    USE SIGNAL ;
    PORT
      LAYER met2 ;
        RECT 395.690 0.000 395.970 4.000 ;
    END
  END X_real[44]
  PIN X_real[45]
    DIRECTION OUTPUT TRISTATE ;
    USE SIGNAL ;
    PORT
      LAYER met2 ;
        RECT 683.190 0.000 683.470 4.000 ;
    END
  END X_real[45]
  PIN X_real[46]
    DIRECTION OUTPUT TRISTATE ;
    USE SIGNAL ;
    PORT
      LAYER met2 ;
        RECT 170.290 0.000 170.570 4.000 ;
    END
  END X_real[46]
  PIN X_real[47]
    DIRECTION OUTPUT TRISTATE ;
    USE SIGNAL ;
    PORT
      LAYER met2 ;
        RECT 607.290 0.000 607.570 4.000 ;
    END
  END X_real[47]
  PIN X_real[48]
    DIRECTION OUTPUT TRISTATE ;
    USE SIGNAL ;
    PORT
      LAYER met2 ;
        RECT 112.790 0.000 113.070 4.000 ;
    END
  END X_real[48]
  PIN X_real[49]
    DIRECTION OUTPUT TRISTATE ;
    USE SIGNAL ;
    PORT
      LAYER met2 ;
        RECT 124.290 730.740 124.570 734.740 ;
    END
  END X_real[49]
  PIN X_real[4]
    DIRECTION OUTPUT TRISTATE ;
    USE SIGNAL ;
    PORT
      LAYER met2 ;
        RECT 634.890 0.000 635.170 4.000 ;
    END
  END X_real[4]
  PIN X_real[50]
    DIRECTION OUTPUT TRISTATE ;
    USE SIGNAL ;
    PORT
      LAYER met2 ;
        RECT 680.890 730.740 681.170 734.740 ;
    END
  END X_real[50]
  PIN X_real[51]
    DIRECTION OUTPUT TRISTATE ;
    USE SIGNAL ;
    PORT
      LAYER met2 ;
        RECT 156.490 0.000 156.770 4.000 ;
    END
  END X_real[51]
  PIN X_real[52]
    DIRECTION OUTPUT TRISTATE ;
    USE SIGNAL ;
    PORT
      LAYER met3 ;
        RECT 720.020 244.840 724.020 245.440 ;
    END
  END X_real[52]
  PIN X_real[53]
    DIRECTION OUTPUT TRISTATE ;
    USE SIGNAL ;
    PORT
      LAYER met2 ;
        RECT 625.690 0.000 625.970 4.000 ;
    END
  END X_real[53]
  PIN X_real[54]
    DIRECTION OUTPUT TRISTATE ;
    USE SIGNAL ;
    PORT
      LAYER met2 ;
        RECT 407.190 0.000 407.470 4.000 ;
    END
  END X_real[54]
  PIN X_real[55]
    DIRECTION OUTPUT TRISTATE ;
    USE SIGNAL ;
    PORT
      LAYER met3 ;
        RECT 720.020 153.040 724.020 153.640 ;
    END
  END X_real[55]
  PIN X_real[56]
    DIRECTION OUTPUT TRISTATE ;
    USE SIGNAL ;
    PORT
      LAYER met2 ;
        RECT 71.390 0.000 71.670 4.000 ;
    END
  END X_real[56]
  PIN X_real[57]
    DIRECTION OUTPUT TRISTATE ;
    USE SIGNAL ;
    PORT
      LAYER met2 ;
        RECT 391.090 0.000 391.370 4.000 ;
    END
  END X_real[57]
  PIN X_real[58]
    DIRECTION OUTPUT TRISTATE ;
    USE SIGNAL ;
    PORT
      LAYER met3 ;
        RECT 0.000 47.640 4.000 48.240 ;
    END
  END X_real[58]
  PIN X_real[59]
    DIRECTION OUTPUT TRISTATE ;
    USE SIGNAL ;
    PORT
      LAYER met2 ;
        RECT 708.490 730.740 708.770 734.740 ;
    END
  END X_real[59]
  PIN X_real[5]
    DIRECTION OUTPUT TRISTATE ;
    USE SIGNAL ;
    PORT
      LAYER met3 ;
        RECT 720.020 231.240 724.020 231.840 ;
    END
  END X_real[5]
  PIN X_real[60]
    DIRECTION OUTPUT TRISTATE ;
    USE SIGNAL ;
    PORT
      LAYER met2 ;
        RECT 29.990 730.740 30.270 734.740 ;
    END
  END X_real[60]
  PIN X_real[61]
    DIRECTION OUTPUT TRISTATE ;
    USE SIGNAL ;
    PORT
      LAYER met3 ;
        RECT 0.000 428.440 4.000 429.040 ;
    END
  END X_real[61]
  PIN X_real[62]
    DIRECTION OUTPUT TRISTATE ;
    USE SIGNAL ;
    PORT
      LAYER met3 ;
        RECT 720.020 299.240 724.020 299.840 ;
    END
  END X_real[62]
  PIN X_real[63]
    DIRECTION OUTPUT TRISTATE ;
    USE SIGNAL ;
    PORT
      LAYER met2 ;
        RECT 218.590 0.000 218.870 4.000 ;
    END
  END X_real[63]
  PIN X_real[64]
    DIRECTION OUTPUT TRISTATE ;
    USE SIGNAL ;
    PORT
      LAYER met2 ;
        RECT 181.790 0.000 182.070 4.000 ;
    END
  END X_real[64]
  PIN X_real[65]
    DIRECTION OUTPUT TRISTATE ;
    USE SIGNAL ;
    PORT
      LAYER met2 ;
        RECT 41.490 0.000 41.770 4.000 ;
    END
  END X_real[65]
  PIN X_real[66]
    DIRECTION OUTPUT TRISTATE ;
    USE SIGNAL ;
    PORT
      LAYER met2 ;
        RECT 285.290 0.000 285.570 4.000 ;
    END
  END X_real[66]
  PIN X_real[67]
    DIRECTION OUTPUT TRISTATE ;
    USE SIGNAL ;
    PORT
      LAYER met2 ;
        RECT 508.390 730.740 508.670 734.740 ;
    END
  END X_real[67]
  PIN X_real[68]
    DIRECTION OUTPUT TRISTATE ;
    USE SIGNAL ;
    PORT
      LAYER met2 ;
        RECT 144.990 730.740 145.270 734.740 ;
    END
  END X_real[68]
  PIN X_real[69]
    DIRECTION OUTPUT TRISTATE ;
    USE SIGNAL ;
    PORT
      LAYER met3 ;
        RECT 0.000 707.240 4.000 707.840 ;
    END
  END X_real[69]
  PIN X_real[6]
    DIRECTION OUTPUT TRISTATE ;
    USE SIGNAL ;
    PORT
      LAYER met3 ;
        RECT 720.020 656.240 724.020 656.840 ;
    END
  END X_real[6]
  PIN X_real[70]
    DIRECTION OUTPUT TRISTATE ;
    USE SIGNAL ;
    PORT
      LAYER met2 ;
        RECT 57.590 730.740 57.870 734.740 ;
    END
  END X_real[70]
  PIN X_real[71]
    DIRECTION OUTPUT TRISTATE ;
    USE SIGNAL ;
    PORT
      LAYER met3 ;
        RECT 720.020 122.440 724.020 123.040 ;
    END
  END X_real[71]
  PIN X_real[72]
    DIRECTION OUTPUT TRISTATE ;
    USE SIGNAL ;
    PORT
      LAYER met2 ;
        RECT 239.290 730.740 239.570 734.740 ;
    END
  END X_real[72]
  PIN X_real[73]
    DIRECTION OUTPUT TRISTATE ;
    USE SIGNAL ;
    PORT
      LAYER met2 ;
        RECT 85.190 730.740 85.470 734.740 ;
    END
  END X_real[73]
  PIN X_real[74]
    DIRECTION OUTPUT TRISTATE ;
    USE SIGNAL ;
    PORT
      LAYER met2 ;
        RECT 204.790 0.000 205.070 4.000 ;
    END
  END X_real[74]
  PIN X_real[75]
    DIRECTION OUTPUT TRISTATE ;
    USE SIGNAL ;
    PORT
      LAYER met3 ;
        RECT 720.020 387.640 724.020 388.240 ;
    END
  END X_real[75]
  PIN X_real[76]
    DIRECTION OUTPUT TRISTATE ;
    USE SIGNAL ;
    PORT
      LAYER met2 ;
        RECT 554.390 0.000 554.670 4.000 ;
    END
  END X_real[76]
  PIN X_real[77]
    DIRECTION OUTPUT TRISTATE ;
    USE SIGNAL ;
    PORT
      LAYER met3 ;
        RECT 0.000 139.440 4.000 140.040 ;
    END
  END X_real[77]
  PIN X_real[78]
    DIRECTION OUTPUT TRISTATE ;
    USE SIGNAL ;
    PORT
      LAYER met2 ;
        RECT 89.790 0.000 90.070 4.000 ;
    END
  END X_real[78]
  PIN X_real[79]
    DIRECTION OUTPUT TRISTATE ;
    USE SIGNAL ;
    PORT
      LAYER met3 ;
        RECT 0.000 459.040 4.000 459.640 ;
    END
  END X_real[79]
  PIN X_real[7]
    DIRECTION OUTPUT TRISTATE ;
    USE SIGNAL ;
    PORT
      LAYER met2 ;
        RECT 264.590 730.740 264.870 734.740 ;
    END
  END X_real[7]
  PIN X_real[80]
    DIRECTION OUTPUT TRISTATE ;
    USE SIGNAL ;
    PORT
      LAYER met2 ;
        RECT 549.790 0.000 550.070 4.000 ;
    END
  END X_real[80]
  PIN X_real[81]
    DIRECTION OUTPUT TRISTATE ;
    USE SIGNAL ;
    PORT
      LAYER met3 ;
        RECT 0.000 465.840 4.000 466.440 ;
    END
  END X_real[81]
  PIN X_real[82]
    DIRECTION OUTPUT TRISTATE ;
    USE SIGNAL ;
    PORT
      LAYER met3 ;
        RECT 720.020 68.040 724.020 68.640 ;
    END
  END X_real[82]
  PIN X_real[83]
    DIRECTION OUTPUT TRISTATE ;
    USE SIGNAL ;
    PORT
      LAYER met2 ;
        RECT 584.290 0.000 584.570 4.000 ;
    END
  END X_real[83]
  PIN X_real[84]
    DIRECTION OUTPUT TRISTATE ;
    USE SIGNAL ;
    PORT
      LAYER met3 ;
        RECT 0.000 309.440 4.000 310.040 ;
    END
  END X_real[84]
  PIN X_real[85]
    DIRECTION OUTPUT TRISTATE ;
    USE SIGNAL ;
    PORT
      LAYER met3 ;
        RECT 0.000 571.240 4.000 571.840 ;
    END
  END X_real[85]
  PIN X_real[86]
    DIRECTION OUTPUT TRISTATE ;
    USE SIGNAL ;
    PORT
      LAYER met2 ;
        RECT 621.090 0.000 621.370 4.000 ;
    END
  END X_real[86]
  PIN X_real[87]
    DIRECTION OUTPUT TRISTATE ;
    USE SIGNAL ;
    PORT
      LAYER met2 ;
        RECT 425.590 0.000 425.870 4.000 ;
    END
  END X_real[87]
  PIN X_real[88]
    DIRECTION OUTPUT TRISTATE ;
    USE SIGNAL ;
    PORT
      LAYER met3 ;
        RECT 720.020 394.440 724.020 395.040 ;
    END
  END X_real[88]
  PIN X_real[89]
    DIRECTION OUTPUT TRISTATE ;
    USE SIGNAL ;
    PORT
      LAYER met2 ;
        RECT 59.890 0.000 60.170 4.000 ;
    END
  END X_real[89]
  PIN X_real[8]
    DIRECTION OUTPUT TRISTATE ;
    USE SIGNAL ;
    PORT
      LAYER met3 ;
        RECT 0.000 598.440 4.000 599.040 ;
    END
  END X_real[8]
  PIN X_real[90]
    DIRECTION OUTPUT TRISTATE ;
    USE SIGNAL ;
    PORT
      LAYER met3 ;
        RECT 0.000 615.440 4.000 616.040 ;
    END
  END X_real[90]
  PIN X_real[91]
    DIRECTION OUTPUT TRISTATE ;
    USE SIGNAL ;
    PORT
      LAYER met2 ;
        RECT 690.090 730.740 690.370 734.740 ;
    END
  END X_real[91]
  PIN X_real[92]
    DIRECTION OUTPUT TRISTATE ;
    USE SIGNAL ;
    PORT
      LAYER met2 ;
        RECT 669.390 0.000 669.670 4.000 ;
    END
  END X_real[92]
  PIN X_real[93]
    DIRECTION OUTPUT TRISTATE ;
    USE SIGNAL ;
    PORT
      LAYER met2 ;
        RECT 36.890 0.000 37.170 4.000 ;
    END
  END X_real[93]
  PIN X_real[94]
    DIRECTION OUTPUT TRISTATE ;
    USE SIGNAL ;
    PORT
      LAYER met3 ;
        RECT 720.020 343.440 724.020 344.040 ;
    END
  END X_real[94]
  PIN X_real[95]
    DIRECTION OUTPUT TRISTATE ;
    USE SIGNAL ;
    PORT
      LAYER met3 ;
        RECT 0.000 81.640 4.000 82.240 ;
    END
  END X_real[95]
  PIN X_real[96]
    DIRECTION OUTPUT TRISTATE ;
    USE SIGNAL ;
    PORT
      LAYER met3 ;
        RECT 0.000 98.640 4.000 99.240 ;
    END
  END X_real[96]
  PIN X_real[97]
    DIRECTION OUTPUT TRISTATE ;
    USE SIGNAL ;
    PORT
      LAYER met3 ;
        RECT 720.020 612.040 724.020 612.640 ;
    END
  END X_real[97]
  PIN X_real[98]
    DIRECTION OUTPUT TRISTATE ;
    USE SIGNAL ;
    PORT
      LAYER met2 ;
        RECT 18.490 0.000 18.770 4.000 ;
    END
  END X_real[98]
  PIN X_real[99]
    DIRECTION OUTPUT TRISTATE ;
    USE SIGNAL ;
    PORT
      LAYER met3 ;
        RECT 0.000 394.440 4.000 395.040 ;
    END
  END X_real[99]
  PIN X_real[9]
    DIRECTION OUTPUT TRISTATE ;
    USE SIGNAL ;
    PORT
      LAYER met2 ;
        RECT 80.590 0.000 80.870 4.000 ;
    END
  END X_real[9]
  PIN clk
    DIRECTION INPUT ;
    USE SIGNAL ;
    PORT
      LAYER met2 ;
        RECT 128.890 0.000 129.170 4.000 ;
    END
  END clk
  PIN rst_n
    DIRECTION INPUT ;
    USE SIGNAL ;
    PORT
      LAYER met2 ;
        RECT 526.790 730.740 527.070 734.740 ;
    END
  END rst_n
  PIN valid_in
    DIRECTION INPUT ;
    USE SIGNAL ;
    PORT
      LAYER met2 ;
        RECT 667.090 730.740 667.370 734.740 ;
    END
  END valid_in
  PIN valid_out
    DIRECTION OUTPUT TRISTATE ;
    USE SIGNAL ;
    PORT
      LAYER met2 ;
        RECT 540.590 0.000 540.870 4.000 ;
    END
  END valid_out
  PIN x_imag[0]
    DIRECTION INPUT ;
    USE SIGNAL ;
    PORT
      LAYER met3 ;
        RECT 0.000 635.840 4.000 636.440 ;
    END
  END x_imag[0]
  PIN x_imag[10]
    DIRECTION INPUT ;
    USE SIGNAL ;
    PORT
      LAYER met2 ;
        RECT 664.790 0.000 665.070 4.000 ;
    END
  END x_imag[10]
  PIN x_imag[11]
    DIRECTION INPUT ;
    USE SIGNAL ;
    PORT
      LAYER met2 ;
        RECT 517.590 730.740 517.870 734.740 ;
    END
  END x_imag[11]
  PIN x_imag[12]
    DIRECTION INPUT ;
    USE SIGNAL ;
    PORT
      LAYER met2 ;
        RECT 119.690 0.000 119.970 4.000 ;
    END
  END x_imag[12]
  PIN x_imag[13]
    DIRECTION INPUT ;
    USE SIGNAL ;
    PORT
      LAYER met2 ;
        RECT 694.690 730.740 694.970 734.740 ;
    END
  END x_imag[13]
  PIN x_imag[14]
    DIRECTION INPUT ;
    USE SIGNAL ;
    PORT
      LAYER met2 ;
        RECT 310.590 0.000 310.870 4.000 ;
    END
  END x_imag[14]
  PIN x_imag[15]
    DIRECTION INPUT ;
    USE SIGNAL ;
    PORT
      LAYER met3 ;
        RECT 0.000 401.240 4.000 401.840 ;
    END
  END x_imag[15]
  PIN x_imag[1]
    DIRECTION INPUT ;
    USE SIGNAL ;
    PORT
      LAYER met3 ;
        RECT 720.020 217.640 724.020 218.240 ;
    END
  END x_imag[1]
  PIN x_imag[2]
    DIRECTION INPUT ;
    USE SIGNAL ;
    PORT
      LAYER met3 ;
        RECT 720.020 17.040 724.020 17.640 ;
    END
  END x_imag[2]
  PIN x_imag[3]
    DIRECTION INPUT ;
    USE SIGNAL ;
    PORT
      LAYER met2 ;
        RECT 473.890 0.000 474.170 4.000 ;
    END
  END x_imag[3]
  PIN x_imag[4]
    DIRECTION INPUT ;
    USE SIGNAL ;
    PORT
      LAYER met2 ;
        RECT 347.390 0.000 347.670 4.000 ;
    END
  END x_imag[4]
  PIN x_imag[5]
    DIRECTION INPUT ;
    USE SIGNAL ;
    PORT
      LAYER met2 ;
        RECT 190.990 730.740 191.270 734.740 ;
    END
  END x_imag[5]
  PIN x_imag[6]
    DIRECTION INPUT ;
    USE SIGNAL ;
    PORT
      LAYER met2 ;
        RECT 335.890 730.740 336.170 734.740 ;
    END
  END x_imag[6]
  PIN x_imag[7]
    DIRECTION INPUT ;
    USE SIGNAL ;
    PORT
      LAYER met2 ;
        RECT 522.190 0.000 522.470 4.000 ;
    END
  END x_imag[7]
  PIN x_imag[8]
    DIRECTION INPUT ;
    USE SIGNAL ;
    PORT
      LAYER met3 ;
        RECT 720.020 95.240 724.020 95.840 ;
    END
  END x_imag[8]
  PIN x_imag[9]
    DIRECTION INPUT ;
    USE SIGNAL ;
    PORT
      LAYER met3 ;
        RECT 720.020 605.240 724.020 605.840 ;
    END
  END x_imag[9]
  PIN x_real[0]
    DIRECTION INPUT ;
    USE SIGNAL ;
    PORT
      LAYER met3 ;
        RECT 720.020 251.640 724.020 252.240 ;
    END
  END x_real[0]
  PIN x_real[10]
    DIRECTION INPUT ;
    USE SIGNAL ;
    PORT
      LAYER met3 ;
        RECT 720.020 224.440 724.020 225.040 ;
    END
  END x_real[10]
  PIN x_real[11]
    DIRECTION INPUT ;
    USE SIGNAL ;
    PORT
      LAYER met2 ;
        RECT 602.690 730.740 602.970 734.740 ;
    END
  END x_real[11]
  PIN x_real[12]
    DIRECTION INPUT ;
    USE SIGNAL ;
    PORT
      LAYER met2 ;
        RECT 699.290 0.000 699.570 4.000 ;
    END
  END x_real[12]
  PIN x_real[13]
    DIRECTION INPUT ;
    USE SIGNAL ;
    PORT
      LAYER met2 ;
        RECT 388.790 730.740 389.070 734.740 ;
    END
  END x_real[13]
  PIN x_real[14]
    DIRECTION INPUT ;
    USE SIGNAL ;
    PORT
      LAYER met3 ;
        RECT 720.020 323.040 724.020 323.640 ;
    END
  END x_real[14]
  PIN x_real[15]
    DIRECTION INPUT ;
    USE SIGNAL ;
    PORT
      LAYER met3 ;
        RECT 720.020 584.840 724.020 585.440 ;
    END
  END x_real[15]
  PIN x_real[1]
    DIRECTION INPUT ;
    USE SIGNAL ;
    PORT
      LAYER met2 ;
        RECT 273.790 730.740 274.070 734.740 ;
    END
  END x_real[1]
  PIN x_real[2]
    DIRECTION INPUT ;
    USE SIGNAL ;
    PORT
      LAYER met3 ;
        RECT 0.000 452.240 4.000 452.840 ;
    END
  END x_real[2]
  PIN x_real[3]
    DIRECTION INPUT ;
    USE SIGNAL ;
    PORT
      LAYER met2 ;
        RECT 673.990 0.000 674.270 4.000 ;
    END
  END x_real[3]
  PIN x_real[4]
    DIRECTION INPUT ;
    USE SIGNAL ;
    PORT
      LAYER met2 ;
        RECT 703.890 730.740 704.170 734.740 ;
    END
  END x_real[4]
  PIN x_real[5]
    DIRECTION INPUT ;
    USE SIGNAL ;
    PORT
      LAYER met2 ;
        RECT 448.590 0.000 448.870 4.000 ;
    END
  END x_real[5]
  PIN x_real[6]
    DIRECTION INPUT ;
    USE SIGNAL ;
    PORT
      LAYER met3 ;
        RECT 720.020 108.840 724.020 109.440 ;
    END
  END x_real[6]
  PIN x_real[7]
    DIRECTION INPUT ;
    USE SIGNAL ;
    PORT
      LAYER met2 ;
        RECT 588.890 730.740 589.170 734.740 ;
    END
  END x_real[7]
  PIN x_real[8]
    DIRECTION INPUT ;
    USE SIGNAL ;
    PORT
      LAYER met3 ;
        RECT 720.020 649.440 724.020 650.040 ;
    END
  END x_real[8]
  PIN x_real[9]
    DIRECTION INPUT ;
    USE SIGNAL ;
    PORT
      LAYER met2 ;
        RECT 46.090 0.000 46.370 4.000 ;
    END
  END x_real[9]
  PIN VPWR
    DIRECTION INOUT ;
    USE POWER ;
    PORT
      LAYER met4 ;
        RECT 635.440 10.640 637.040 723.760 ;
    END
  END VPWR
  PIN VPWR
    DIRECTION INOUT ;
    USE POWER ;
    PORT
      LAYER met4 ;
        RECT 481.840 10.640 483.440 723.760 ;
    END
  END VPWR
  PIN VPWR
    DIRECTION INOUT ;
    USE POWER ;
    PORT
      LAYER met4 ;
        RECT 328.240 10.640 329.840 723.760 ;
    END
  END VPWR
  PIN VPWR
    DIRECTION INOUT ;
    USE POWER ;
    PORT
      LAYER met4 ;
        RECT 174.640 10.640 176.240 723.760 ;
    END
  END VPWR
  PIN VPWR
    DIRECTION INOUT ;
    USE POWER ;
    PORT
      LAYER met4 ;
        RECT 21.040 10.640 22.640 723.760 ;
    END
  END VPWR
  PIN VPWR
    DIRECTION INOUT ;
    USE POWER ;
    PORT
      LAYER met5 ;
        RECT 5.520 639.210 718.060 640.810 ;
    END
  END VPWR
  PIN VPWR
    DIRECTION INOUT ;
    USE POWER ;
    PORT
      LAYER met5 ;
        RECT 5.520 486.030 718.060 487.630 ;
    END
  END VPWR
  PIN VPWR
    DIRECTION INOUT ;
    USE POWER ;
    PORT
      LAYER met5 ;
        RECT 5.520 332.850 718.060 334.450 ;
    END
  END VPWR
  PIN VPWR
    DIRECTION INOUT ;
    USE POWER ;
    PORT
      LAYER met5 ;
        RECT 5.520 179.670 718.060 181.270 ;
    END
  END VPWR
  PIN VPWR
    DIRECTION INOUT ;
    USE POWER ;
    PORT
      LAYER met5 ;
        RECT 5.520 26.490 718.060 28.090 ;
    END
  END VPWR
  PIN VGND
    DIRECTION INOUT ;
    USE GROUND ;
    PORT
      LAYER met4 ;
        RECT 712.240 10.640 713.840 723.760 ;
    END
  END VGND
  PIN VGND
    DIRECTION INOUT ;
    USE GROUND ;
    PORT
      LAYER met4 ;
        RECT 558.640 10.640 560.240 723.760 ;
    END
  END VGND
  PIN VGND
    DIRECTION INOUT ;
    USE GROUND ;
    PORT
      LAYER met4 ;
        RECT 405.040 10.640 406.640 723.760 ;
    END
  END VGND
  PIN VGND
    DIRECTION INOUT ;
    USE GROUND ;
    PORT
      LAYER met4 ;
        RECT 251.440 10.640 253.040 723.760 ;
    END
  END VGND
  PIN VGND
    DIRECTION INOUT ;
    USE GROUND ;
    PORT
      LAYER met4 ;
        RECT 97.840 10.640 99.440 723.760 ;
    END
  END VGND
  PIN VGND
    DIRECTION INOUT ;
    USE GROUND ;
    PORT
      LAYER met5 ;
        RECT 5.520 715.800 718.060 717.400 ;
    END
  END VGND
  PIN VGND
    DIRECTION INOUT ;
    USE GROUND ;
    PORT
      LAYER met5 ;
        RECT 5.520 562.620 718.060 564.220 ;
    END
  END VGND
  PIN VGND
    DIRECTION INOUT ;
    USE GROUND ;
    PORT
      LAYER met5 ;
        RECT 5.520 409.440 718.060 411.040 ;
    END
  END VGND
  PIN VGND
    DIRECTION INOUT ;
    USE GROUND ;
    PORT
      LAYER met5 ;
        RECT 5.520 256.260 718.060 257.860 ;
    END
  END VGND
  PIN VGND
    DIRECTION INOUT ;
    USE GROUND ;
    PORT
      LAYER met5 ;
        RECT 5.520 103.080 718.060 104.680 ;
    END
  END VGND
  OBS
      LAYER li1 ;
        RECT 5.520 9.605 718.835 723.605 ;
      LAYER met1 ;
        RECT 2.370 7.520 720.290 724.500 ;
      LAYER met2 ;
        RECT 2.400 730.460 4.410 730.740 ;
        RECT 5.250 730.460 9.010 730.740 ;
        RECT 9.850 730.460 13.610 730.740 ;
        RECT 14.450 730.460 18.210 730.740 ;
        RECT 19.050 730.460 22.810 730.740 ;
        RECT 23.650 730.460 27.410 730.740 ;
        RECT 28.250 730.460 29.710 730.740 ;
        RECT 30.550 730.460 34.310 730.740 ;
        RECT 35.150 730.460 38.910 730.740 ;
        RECT 39.750 730.460 43.510 730.740 ;
        RECT 44.350 730.460 48.110 730.740 ;
        RECT 48.950 730.460 52.710 730.740 ;
        RECT 53.550 730.460 57.310 730.740 ;
        RECT 58.150 730.460 61.910 730.740 ;
        RECT 62.750 730.460 66.510 730.740 ;
        RECT 67.350 730.460 71.110 730.740 ;
        RECT 71.950 730.460 75.710 730.740 ;
        RECT 76.550 730.460 80.310 730.740 ;
        RECT 81.150 730.460 84.910 730.740 ;
        RECT 85.750 730.460 87.210 730.740 ;
        RECT 88.050 730.460 91.810 730.740 ;
        RECT 92.650 730.460 96.410 730.740 ;
        RECT 97.250 730.460 101.010 730.740 ;
        RECT 101.850 730.460 105.610 730.740 ;
        RECT 106.450 730.460 110.210 730.740 ;
        RECT 111.050 730.460 114.810 730.740 ;
        RECT 115.650 730.460 119.410 730.740 ;
        RECT 120.250 730.460 124.010 730.740 ;
        RECT 124.850 730.460 128.610 730.740 ;
        RECT 129.450 730.460 133.210 730.740 ;
        RECT 134.050 730.460 137.810 730.740 ;
        RECT 138.650 730.460 142.410 730.740 ;
        RECT 143.250 730.460 144.710 730.740 ;
        RECT 145.550 730.460 149.310 730.740 ;
        RECT 150.150 730.460 153.910 730.740 ;
        RECT 154.750 730.460 158.510 730.740 ;
        RECT 159.350 730.460 163.110 730.740 ;
        RECT 163.950 730.460 167.710 730.740 ;
        RECT 168.550 730.460 172.310 730.740 ;
        RECT 173.150 730.460 176.910 730.740 ;
        RECT 177.750 730.460 181.510 730.740 ;
        RECT 182.350 730.460 186.110 730.740 ;
        RECT 186.950 730.460 190.710 730.740 ;
        RECT 191.550 730.460 195.310 730.740 ;
        RECT 196.150 730.460 199.910 730.740 ;
        RECT 200.750 730.460 202.210 730.740 ;
        RECT 203.050 730.460 206.810 730.740 ;
        RECT 207.650 730.460 211.410 730.740 ;
        RECT 212.250 730.460 216.010 730.740 ;
        RECT 216.850 730.460 220.610 730.740 ;
        RECT 221.450 730.460 225.210 730.740 ;
        RECT 226.050 730.460 229.810 730.740 ;
        RECT 230.650 730.460 234.410 730.740 ;
        RECT 235.250 730.460 239.010 730.740 ;
        RECT 239.850 730.460 243.610 730.740 ;
        RECT 244.450 730.460 248.210 730.740 ;
        RECT 249.050 730.460 252.810 730.740 ;
        RECT 253.650 730.460 257.410 730.740 ;
        RECT 258.250 730.460 259.710 730.740 ;
        RECT 260.550 730.460 264.310 730.740 ;
        RECT 265.150 730.460 268.910 730.740 ;
        RECT 269.750 730.460 273.510 730.740 ;
        RECT 274.350 730.460 278.110 730.740 ;
        RECT 278.950 730.460 282.710 730.740 ;
        RECT 283.550 730.460 287.310 730.740 ;
        RECT 288.150 730.460 291.910 730.740 ;
        RECT 292.750 730.460 296.510 730.740 ;
        RECT 297.350 730.460 301.110 730.740 ;
        RECT 301.950 730.460 305.710 730.740 ;
        RECT 306.550 730.460 310.310 730.740 ;
        RECT 311.150 730.460 314.910 730.740 ;
        RECT 315.750 730.460 317.210 730.740 ;
        RECT 318.050 730.460 321.810 730.740 ;
        RECT 322.650 730.460 326.410 730.740 ;
        RECT 327.250 730.460 331.010 730.740 ;
        RECT 331.850 730.460 335.610 730.740 ;
        RECT 336.450 730.460 340.210 730.740 ;
        RECT 341.050 730.460 344.810 730.740 ;
        RECT 345.650 730.460 349.410 730.740 ;
        RECT 350.250 730.460 354.010 730.740 ;
        RECT 354.850 730.460 358.610 730.740 ;
        RECT 359.450 730.460 363.210 730.740 ;
        RECT 364.050 730.460 367.810 730.740 ;
        RECT 368.650 730.460 372.410 730.740 ;
        RECT 373.250 730.460 374.710 730.740 ;
        RECT 375.550 730.460 379.310 730.740 ;
        RECT 380.150 730.460 383.910 730.740 ;
        RECT 384.750 730.460 388.510 730.740 ;
        RECT 389.350 730.460 393.110 730.740 ;
        RECT 393.950 730.460 397.710 730.740 ;
        RECT 398.550 730.460 402.310 730.740 ;
        RECT 403.150 730.460 406.910 730.740 ;
        RECT 407.750 730.460 411.510 730.740 ;
        RECT 412.350 730.460 416.110 730.740 ;
        RECT 416.950 730.460 420.710 730.740 ;
        RECT 421.550 730.460 425.310 730.740 ;
        RECT 426.150 730.460 429.910 730.740 ;
        RECT 430.750 730.460 432.210 730.740 ;
        RECT 433.050 730.460 436.810 730.740 ;
        RECT 437.650 730.460 441.410 730.740 ;
        RECT 442.250 730.460 446.010 730.740 ;
        RECT 446.850 730.460 450.610 730.740 ;
        RECT 451.450 730.460 455.210 730.740 ;
        RECT 456.050 730.460 459.810 730.740 ;
        RECT 460.650 730.460 464.410 730.740 ;
        RECT 465.250 730.460 469.010 730.740 ;
        RECT 469.850 730.460 473.610 730.740 ;
        RECT 474.450 730.460 478.210 730.740 ;
        RECT 479.050 730.460 482.810 730.740 ;
        RECT 483.650 730.460 487.410 730.740 ;
        RECT 488.250 730.460 489.710 730.740 ;
        RECT 490.550 730.460 494.310 730.740 ;
        RECT 495.150 730.460 498.910 730.740 ;
        RECT 499.750 730.460 503.510 730.740 ;
        RECT 504.350 730.460 508.110 730.740 ;
        RECT 508.950 730.460 512.710 730.740 ;
        RECT 513.550 730.460 517.310 730.740 ;
        RECT 518.150 730.460 521.910 730.740 ;
        RECT 522.750 730.460 526.510 730.740 ;
        RECT 527.350 730.460 531.110 730.740 ;
        RECT 531.950 730.460 535.710 730.740 ;
        RECT 536.550 730.460 540.310 730.740 ;
        RECT 541.150 730.460 544.910 730.740 ;
        RECT 545.750 730.460 547.210 730.740 ;
        RECT 548.050 730.460 551.810 730.740 ;
        RECT 552.650 730.460 556.410 730.740 ;
        RECT 557.250 730.460 561.010 730.740 ;
        RECT 561.850 730.460 565.610 730.740 ;
        RECT 566.450 730.460 570.210 730.740 ;
        RECT 571.050 730.460 574.810 730.740 ;
        RECT 575.650 730.460 579.410 730.740 ;
        RECT 580.250 730.460 584.010 730.740 ;
        RECT 584.850 730.460 588.610 730.740 ;
        RECT 589.450 730.460 593.210 730.740 ;
        RECT 594.050 730.460 597.810 730.740 ;
        RECT 598.650 730.460 602.410 730.740 ;
        RECT 603.250 730.460 604.710 730.740 ;
        RECT 605.550 730.460 609.310 730.740 ;
        RECT 610.150 730.460 613.910 730.740 ;
        RECT 614.750 730.460 618.510 730.740 ;
        RECT 619.350 730.460 623.110 730.740 ;
        RECT 623.950 730.460 627.710 730.740 ;
        RECT 628.550 730.460 632.310 730.740 ;
        RECT 633.150 730.460 636.910 730.740 ;
        RECT 637.750 730.460 641.510 730.740 ;
        RECT 642.350 730.460 646.110 730.740 ;
        RECT 646.950 730.460 650.710 730.740 ;
        RECT 651.550 730.460 655.310 730.740 ;
        RECT 656.150 730.460 659.910 730.740 ;
        RECT 660.750 730.460 662.210 730.740 ;
        RECT 663.050 730.460 666.810 730.740 ;
        RECT 667.650 730.460 671.410 730.740 ;
        RECT 672.250 730.460 676.010 730.740 ;
        RECT 676.850 730.460 680.610 730.740 ;
        RECT 681.450 730.460 685.210 730.740 ;
        RECT 686.050 730.460 689.810 730.740 ;
        RECT 690.650 730.460 694.410 730.740 ;
        RECT 695.250 730.460 699.010 730.740 ;
        RECT 699.850 730.460 703.610 730.740 ;
        RECT 704.450 730.460 708.210 730.740 ;
        RECT 709.050 730.460 712.810 730.740 ;
        RECT 713.650 730.460 717.410 730.740 ;
        RECT 718.250 730.460 719.710 730.740 ;
        RECT 2.400 4.280 720.260 730.460 ;
        RECT 2.950 3.555 4.410 4.280 ;
        RECT 5.250 3.555 9.010 4.280 ;
        RECT 9.850 3.555 13.610 4.280 ;
        RECT 14.450 3.555 18.210 4.280 ;
        RECT 19.050 3.555 22.810 4.280 ;
        RECT 23.650 3.555 27.410 4.280 ;
        RECT 28.250 3.555 32.010 4.280 ;
        RECT 32.850 3.555 36.610 4.280 ;
        RECT 37.450 3.555 41.210 4.280 ;
        RECT 42.050 3.555 45.810 4.280 ;
        RECT 46.650 3.555 50.410 4.280 ;
        RECT 51.250 3.555 55.010 4.280 ;
        RECT 55.850 3.555 59.610 4.280 ;
        RECT 60.450 3.555 61.910 4.280 ;
        RECT 62.750 3.555 66.510 4.280 ;
        RECT 67.350 3.555 71.110 4.280 ;
        RECT 71.950 3.555 75.710 4.280 ;
        RECT 76.550 3.555 80.310 4.280 ;
        RECT 81.150 3.555 84.910 4.280 ;
        RECT 85.750 3.555 89.510 4.280 ;
        RECT 90.350 3.555 94.110 4.280 ;
        RECT 94.950 3.555 98.710 4.280 ;
        RECT 99.550 3.555 103.310 4.280 ;
        RECT 104.150 3.555 107.910 4.280 ;
        RECT 108.750 3.555 112.510 4.280 ;
        RECT 113.350 3.555 117.110 4.280 ;
        RECT 117.950 3.555 119.410 4.280 ;
        RECT 120.250 3.555 124.010 4.280 ;
        RECT 124.850 3.555 128.610 4.280 ;
        RECT 129.450 3.555 133.210 4.280 ;
        RECT 134.050 3.555 137.810 4.280 ;
        RECT 138.650 3.555 142.410 4.280 ;
        RECT 143.250 3.555 147.010 4.280 ;
        RECT 147.850 3.555 151.610 4.280 ;
        RECT 152.450 3.555 156.210 4.280 ;
        RECT 157.050 3.555 160.810 4.280 ;
        RECT 161.650 3.555 165.410 4.280 ;
        RECT 166.250 3.555 170.010 4.280 ;
        RECT 170.850 3.555 174.610 4.280 ;
        RECT 175.450 3.555 176.910 4.280 ;
        RECT 177.750 3.555 181.510 4.280 ;
        RECT 182.350 3.555 186.110 4.280 ;
        RECT 186.950 3.555 190.710 4.280 ;
        RECT 191.550 3.555 195.310 4.280 ;
        RECT 196.150 3.555 199.910 4.280 ;
        RECT 200.750 3.555 204.510 4.280 ;
        RECT 205.350 3.555 209.110 4.280 ;
        RECT 209.950 3.555 213.710 4.280 ;
        RECT 214.550 3.555 218.310 4.280 ;
        RECT 219.150 3.555 222.910 4.280 ;
        RECT 223.750 3.555 227.510 4.280 ;
        RECT 228.350 3.555 232.110 4.280 ;
        RECT 232.950 3.555 234.410 4.280 ;
        RECT 235.250 3.555 239.010 4.280 ;
        RECT 239.850 3.555 243.610 4.280 ;
        RECT 244.450 3.555 248.210 4.280 ;
        RECT 249.050 3.555 252.810 4.280 ;
        RECT 253.650 3.555 257.410 4.280 ;
        RECT 258.250 3.555 262.010 4.280 ;
        RECT 262.850 3.555 266.610 4.280 ;
        RECT 267.450 3.555 271.210 4.280 ;
        RECT 272.050 3.555 275.810 4.280 ;
        RECT 276.650 3.555 280.410 4.280 ;
        RECT 281.250 3.555 285.010 4.280 ;
        RECT 285.850 3.555 289.610 4.280 ;
        RECT 290.450 3.555 291.910 4.280 ;
        RECT 292.750 3.555 296.510 4.280 ;
        RECT 297.350 3.555 301.110 4.280 ;
        RECT 301.950 3.555 305.710 4.280 ;
        RECT 306.550 3.555 310.310 4.280 ;
        RECT 311.150 3.555 314.910 4.280 ;
        RECT 315.750 3.555 319.510 4.280 ;
        RECT 320.350 3.555 324.110 4.280 ;
        RECT 324.950 3.555 328.710 4.280 ;
        RECT 329.550 3.555 333.310 4.280 ;
        RECT 334.150 3.555 337.910 4.280 ;
        RECT 338.750 3.555 342.510 4.280 ;
        RECT 343.350 3.555 347.110 4.280 ;
        RECT 347.950 3.555 349.410 4.280 ;
        RECT 350.250 3.555 354.010 4.280 ;
        RECT 354.850 3.555 358.610 4.280 ;
        RECT 359.450 3.555 363.210 4.280 ;
        RECT 364.050 3.555 367.810 4.280 ;
        RECT 368.650 3.555 372.410 4.280 ;
        RECT 373.250 3.555 377.010 4.280 ;
        RECT 377.850 3.555 381.610 4.280 ;
        RECT 382.450 3.555 386.210 4.280 ;
        RECT 387.050 3.555 390.810 4.280 ;
        RECT 391.650 3.555 395.410 4.280 ;
        RECT 396.250 3.555 400.010 4.280 ;
        RECT 400.850 3.555 404.610 4.280 ;
        RECT 405.450 3.555 406.910 4.280 ;
        RECT 407.750 3.555 411.510 4.280 ;
        RECT 412.350 3.555 416.110 4.280 ;
        RECT 416.950 3.555 420.710 4.280 ;
        RECT 421.550 3.555 425.310 4.280 ;
        RECT 426.150 3.555 429.910 4.280 ;
        RECT 430.750 3.555 434.510 4.280 ;
        RECT 435.350 3.555 439.110 4.280 ;
        RECT 439.950 3.555 443.710 4.280 ;
        RECT 444.550 3.555 448.310 4.280 ;
        RECT 449.150 3.555 452.910 4.280 ;
        RECT 453.750 3.555 457.510 4.280 ;
        RECT 458.350 3.555 462.110 4.280 ;
        RECT 462.950 3.555 464.410 4.280 ;
        RECT 465.250 3.555 469.010 4.280 ;
        RECT 469.850 3.555 473.610 4.280 ;
        RECT 474.450 3.555 478.210 4.280 ;
        RECT 479.050 3.555 482.810 4.280 ;
        RECT 483.650 3.555 487.410 4.280 ;
        RECT 488.250 3.555 492.010 4.280 ;
        RECT 492.850 3.555 496.610 4.280 ;
        RECT 497.450 3.555 501.210 4.280 ;
        RECT 502.050 3.555 505.810 4.280 ;
        RECT 506.650 3.555 510.410 4.280 ;
        RECT 511.250 3.555 515.010 4.280 ;
        RECT 515.850 3.555 519.610 4.280 ;
        RECT 520.450 3.555 521.910 4.280 ;
        RECT 522.750 3.555 526.510 4.280 ;
        RECT 527.350 3.555 531.110 4.280 ;
        RECT 531.950 3.555 535.710 4.280 ;
        RECT 536.550 3.555 540.310 4.280 ;
        RECT 541.150 3.555 544.910 4.280 ;
        RECT 545.750 3.555 549.510 4.280 ;
        RECT 550.350 3.555 554.110 4.280 ;
        RECT 554.950 3.555 558.710 4.280 ;
        RECT 559.550 3.555 563.310 4.280 ;
        RECT 564.150 3.555 567.910 4.280 ;
        RECT 568.750 3.555 572.510 4.280 ;
        RECT 573.350 3.555 577.110 4.280 ;
        RECT 577.950 3.555 579.410 4.280 ;
        RECT 580.250 3.555 584.010 4.280 ;
        RECT 584.850 3.555 588.610 4.280 ;
        RECT 589.450 3.555 593.210 4.280 ;
        RECT 594.050 3.555 597.810 4.280 ;
        RECT 598.650 3.555 602.410 4.280 ;
        RECT 603.250 3.555 607.010 4.280 ;
        RECT 607.850 3.555 611.610 4.280 ;
        RECT 612.450 3.555 616.210 4.280 ;
        RECT 617.050 3.555 620.810 4.280 ;
        RECT 621.650 3.555 625.410 4.280 ;
        RECT 626.250 3.555 630.010 4.280 ;
        RECT 630.850 3.555 634.610 4.280 ;
        RECT 635.450 3.555 636.910 4.280 ;
        RECT 637.750 3.555 641.510 4.280 ;
        RECT 642.350 3.555 646.110 4.280 ;
        RECT 646.950 3.555 650.710 4.280 ;
        RECT 651.550 3.555 655.310 4.280 ;
        RECT 656.150 3.555 659.910 4.280 ;
        RECT 660.750 3.555 664.510 4.280 ;
        RECT 665.350 3.555 669.110 4.280 ;
        RECT 669.950 3.555 673.710 4.280 ;
        RECT 674.550 3.555 678.310 4.280 ;
        RECT 679.150 3.555 682.910 4.280 ;
        RECT 683.750 3.555 687.510 4.280 ;
        RECT 688.350 3.555 692.110 4.280 ;
        RECT 692.950 3.555 694.410 4.280 ;
        RECT 695.250 3.555 699.010 4.280 ;
        RECT 699.850 3.555 703.610 4.280 ;
        RECT 704.450 3.555 708.210 4.280 ;
        RECT 709.050 3.555 712.810 4.280 ;
        RECT 713.650 3.555 717.410 4.280 ;
        RECT 718.250 3.555 720.260 4.280 ;
      LAYER met3 ;
        RECT 4.400 727.240 720.020 728.105 ;
        RECT 4.000 725.240 720.020 727.240 ;
        RECT 4.000 723.840 719.620 725.240 ;
        RECT 4.000 721.840 720.020 723.840 ;
        RECT 4.400 720.440 720.020 721.840 ;
        RECT 4.000 718.440 720.020 720.440 ;
        RECT 4.000 717.040 719.620 718.440 ;
        RECT 4.000 715.040 720.020 717.040 ;
        RECT 4.400 713.640 720.020 715.040 ;
        RECT 4.000 711.640 720.020 713.640 ;
        RECT 4.000 710.240 719.620 711.640 ;
        RECT 4.000 708.240 720.020 710.240 ;
        RECT 4.400 706.840 720.020 708.240 ;
        RECT 4.000 704.840 720.020 706.840 ;
        RECT 4.000 703.440 719.620 704.840 ;
        RECT 4.000 701.440 720.020 703.440 ;
        RECT 4.400 700.040 720.020 701.440 ;
        RECT 4.000 698.040 720.020 700.040 ;
        RECT 4.000 696.640 719.620 698.040 ;
        RECT 4.000 694.640 720.020 696.640 ;
        RECT 4.400 693.240 720.020 694.640 ;
        RECT 4.000 691.240 720.020 693.240 ;
        RECT 4.000 689.840 719.620 691.240 ;
        RECT 4.000 687.840 720.020 689.840 ;
        RECT 4.400 686.440 720.020 687.840 ;
        RECT 4.000 684.440 720.020 686.440 ;
        RECT 4.400 683.040 719.620 684.440 ;
        RECT 4.000 677.640 720.020 683.040 ;
        RECT 4.400 676.240 719.620 677.640 ;
        RECT 4.000 670.840 720.020 676.240 ;
        RECT 4.400 669.440 719.620 670.840 ;
        RECT 4.000 664.040 720.020 669.440 ;
        RECT 4.400 662.640 719.620 664.040 ;
        RECT 4.000 657.240 720.020 662.640 ;
        RECT 4.400 655.840 719.620 657.240 ;
        RECT 4.000 650.440 720.020 655.840 ;
        RECT 4.400 649.040 719.620 650.440 ;
        RECT 4.000 643.640 720.020 649.040 ;
        RECT 4.400 642.240 719.620 643.640 ;
        RECT 4.000 640.240 720.020 642.240 ;
        RECT 4.000 638.840 719.620 640.240 ;
        RECT 4.000 636.840 720.020 638.840 ;
        RECT 4.400 635.440 720.020 636.840 ;
        RECT 4.000 633.440 720.020 635.440 ;
        RECT 4.000 632.040 719.620 633.440 ;
        RECT 4.000 630.040 720.020 632.040 ;
        RECT 4.400 628.640 720.020 630.040 ;
        RECT 4.000 626.640 720.020 628.640 ;
        RECT 4.000 625.240 719.620 626.640 ;
        RECT 4.000 623.240 720.020 625.240 ;
        RECT 4.400 621.840 720.020 623.240 ;
        RECT 4.000 619.840 720.020 621.840 ;
        RECT 4.000 618.440 719.620 619.840 ;
        RECT 4.000 616.440 720.020 618.440 ;
        RECT 4.400 615.040 720.020 616.440 ;
        RECT 4.000 613.040 720.020 615.040 ;
        RECT 4.000 611.640 719.620 613.040 ;
        RECT 4.000 609.640 720.020 611.640 ;
        RECT 4.400 608.240 720.020 609.640 ;
        RECT 4.000 606.240 720.020 608.240 ;
        RECT 4.000 604.840 719.620 606.240 ;
        RECT 4.000 602.840 720.020 604.840 ;
        RECT 4.400 601.440 720.020 602.840 ;
        RECT 4.000 599.440 720.020 601.440 ;
        RECT 4.400 598.040 719.620 599.440 ;
        RECT 4.000 592.640 720.020 598.040 ;
        RECT 4.400 591.240 719.620 592.640 ;
        RECT 4.000 585.840 720.020 591.240 ;
        RECT 4.400 584.440 719.620 585.840 ;
        RECT 4.000 579.040 720.020 584.440 ;
        RECT 4.400 577.640 719.620 579.040 ;
        RECT 4.000 572.240 720.020 577.640 ;
        RECT 4.400 570.840 719.620 572.240 ;
        RECT 4.000 565.440 720.020 570.840 ;
        RECT 4.400 564.040 719.620 565.440 ;
        RECT 4.000 558.640 720.020 564.040 ;
        RECT 4.400 557.240 719.620 558.640 ;
        RECT 4.000 555.240 720.020 557.240 ;
        RECT 4.000 553.840 719.620 555.240 ;
        RECT 4.000 551.840 720.020 553.840 ;
        RECT 4.400 550.440 720.020 551.840 ;
        RECT 4.000 548.440 720.020 550.440 ;
        RECT 4.000 547.040 719.620 548.440 ;
        RECT 4.000 545.040 720.020 547.040 ;
        RECT 4.400 543.640 720.020 545.040 ;
        RECT 4.000 541.640 720.020 543.640 ;
        RECT 4.000 540.240 719.620 541.640 ;
        RECT 4.000 538.240 720.020 540.240 ;
        RECT 4.400 536.840 720.020 538.240 ;
        RECT 4.000 534.840 720.020 536.840 ;
        RECT 4.000 533.440 719.620 534.840 ;
        RECT 4.000 531.440 720.020 533.440 ;
        RECT 4.400 530.040 720.020 531.440 ;
        RECT 4.000 528.040 720.020 530.040 ;
        RECT 4.000 526.640 719.620 528.040 ;
        RECT 4.000 524.640 720.020 526.640 ;
        RECT 4.400 523.240 720.020 524.640 ;
        RECT 4.000 521.240 720.020 523.240 ;
        RECT 4.000 519.840 719.620 521.240 ;
        RECT 4.000 517.840 720.020 519.840 ;
        RECT 4.400 516.440 720.020 517.840 ;
        RECT 4.000 514.440 720.020 516.440 ;
        RECT 4.400 513.040 719.620 514.440 ;
        RECT 4.000 507.640 720.020 513.040 ;
        RECT 4.400 506.240 719.620 507.640 ;
        RECT 4.000 500.840 720.020 506.240 ;
        RECT 4.400 499.440 719.620 500.840 ;
        RECT 4.000 494.040 720.020 499.440 ;
        RECT 4.400 492.640 719.620 494.040 ;
        RECT 4.000 487.240 720.020 492.640 ;
        RECT 4.400 485.840 719.620 487.240 ;
        RECT 4.000 480.440 720.020 485.840 ;
        RECT 4.400 479.040 719.620 480.440 ;
        RECT 4.000 473.640 720.020 479.040 ;
        RECT 4.400 472.240 719.620 473.640 ;
        RECT 4.000 470.240 720.020 472.240 ;
        RECT 4.000 468.840 719.620 470.240 ;
        RECT 4.000 466.840 720.020 468.840 ;
        RECT 4.400 465.440 720.020 466.840 ;
        RECT 4.000 463.440 720.020 465.440 ;
        RECT 4.000 462.040 719.620 463.440 ;
        RECT 4.000 460.040 720.020 462.040 ;
        RECT 4.400 458.640 720.020 460.040 ;
        RECT 4.000 456.640 720.020 458.640 ;
        RECT 4.000 455.240 719.620 456.640 ;
        RECT 4.000 453.240 720.020 455.240 ;
        RECT 4.400 451.840 720.020 453.240 ;
        RECT 4.000 449.840 720.020 451.840 ;
        RECT 4.000 448.440 719.620 449.840 ;
        RECT 4.000 446.440 720.020 448.440 ;
        RECT 4.400 445.040 720.020 446.440 ;
        RECT 4.000 443.040 720.020 445.040 ;
        RECT 4.000 441.640 719.620 443.040 ;
        RECT 4.000 439.640 720.020 441.640 ;
        RECT 4.400 438.240 720.020 439.640 ;
        RECT 4.000 436.240 720.020 438.240 ;
        RECT 4.000 434.840 719.620 436.240 ;
        RECT 4.000 432.840 720.020 434.840 ;
        RECT 4.400 431.440 720.020 432.840 ;
        RECT 4.000 429.440 720.020 431.440 ;
        RECT 4.400 428.040 719.620 429.440 ;
        RECT 4.000 422.640 720.020 428.040 ;
        RECT 4.400 421.240 719.620 422.640 ;
        RECT 4.000 415.840 720.020 421.240 ;
        RECT 4.400 414.440 719.620 415.840 ;
        RECT 4.000 409.040 720.020 414.440 ;
        RECT 4.400 407.640 719.620 409.040 ;
        RECT 4.000 402.240 720.020 407.640 ;
        RECT 4.400 400.840 719.620 402.240 ;
        RECT 4.000 395.440 720.020 400.840 ;
        RECT 4.400 394.040 719.620 395.440 ;
        RECT 4.000 388.640 720.020 394.040 ;
        RECT 4.400 387.240 719.620 388.640 ;
        RECT 4.000 385.240 720.020 387.240 ;
        RECT 4.000 383.840 719.620 385.240 ;
        RECT 4.000 381.840 720.020 383.840 ;
        RECT 4.400 380.440 720.020 381.840 ;
        RECT 4.000 378.440 720.020 380.440 ;
        RECT 4.000 377.040 719.620 378.440 ;
        RECT 4.000 375.040 720.020 377.040 ;
        RECT 4.400 373.640 720.020 375.040 ;
        RECT 4.000 371.640 720.020 373.640 ;
        RECT 4.000 370.240 719.620 371.640 ;
        RECT 4.000 368.240 720.020 370.240 ;
        RECT 4.400 366.840 720.020 368.240 ;
        RECT 4.000 364.840 720.020 366.840 ;
        RECT 4.000 363.440 719.620 364.840 ;
        RECT 4.000 361.440 720.020 363.440 ;
        RECT 4.400 360.040 720.020 361.440 ;
        RECT 4.000 358.040 720.020 360.040 ;
        RECT 4.000 356.640 719.620 358.040 ;
        RECT 4.000 354.640 720.020 356.640 ;
        RECT 4.400 353.240 720.020 354.640 ;
        RECT 4.000 351.240 720.020 353.240 ;
        RECT 4.000 349.840 719.620 351.240 ;
        RECT 4.000 347.840 720.020 349.840 ;
        RECT 4.400 346.440 720.020 347.840 ;
        RECT 4.000 344.440 720.020 346.440 ;
        RECT 4.400 343.040 719.620 344.440 ;
        RECT 4.000 337.640 720.020 343.040 ;
        RECT 4.400 336.240 719.620 337.640 ;
        RECT 4.000 330.840 720.020 336.240 ;
        RECT 4.400 329.440 719.620 330.840 ;
        RECT 4.000 324.040 720.020 329.440 ;
        RECT 4.400 322.640 719.620 324.040 ;
        RECT 4.000 317.240 720.020 322.640 ;
        RECT 4.400 315.840 719.620 317.240 ;
        RECT 4.000 310.440 720.020 315.840 ;
        RECT 4.400 309.040 719.620 310.440 ;
        RECT 4.000 303.640 720.020 309.040 ;
        RECT 4.400 302.240 719.620 303.640 ;
        RECT 4.000 300.240 720.020 302.240 ;
        RECT 4.000 298.840 719.620 300.240 ;
        RECT 4.000 296.840 720.020 298.840 ;
        RECT 4.400 295.440 720.020 296.840 ;
        RECT 4.000 293.440 720.020 295.440 ;
        RECT 4.000 292.040 719.620 293.440 ;
        RECT 4.000 290.040 720.020 292.040 ;
        RECT 4.400 288.640 720.020 290.040 ;
        RECT 4.000 286.640 720.020 288.640 ;
        RECT 4.000 285.240 719.620 286.640 ;
        RECT 4.000 283.240 720.020 285.240 ;
        RECT 4.400 281.840 720.020 283.240 ;
        RECT 4.000 279.840 720.020 281.840 ;
        RECT 4.000 278.440 719.620 279.840 ;
        RECT 4.000 276.440 720.020 278.440 ;
        RECT 4.400 275.040 720.020 276.440 ;
        RECT 4.000 273.040 720.020 275.040 ;
        RECT 4.000 271.640 719.620 273.040 ;
        RECT 4.000 269.640 720.020 271.640 ;
        RECT 4.400 268.240 720.020 269.640 ;
        RECT 4.000 266.240 720.020 268.240 ;
        RECT 4.000 264.840 719.620 266.240 ;
        RECT 4.000 262.840 720.020 264.840 ;
        RECT 4.400 261.440 720.020 262.840 ;
        RECT 4.000 259.440 720.020 261.440 ;
        RECT 4.400 258.040 719.620 259.440 ;
        RECT 4.000 252.640 720.020 258.040 ;
        RECT 4.400 251.240 719.620 252.640 ;
        RECT 4.000 245.840 720.020 251.240 ;
        RECT 4.400 244.440 719.620 245.840 ;
        RECT 4.000 239.040 720.020 244.440 ;
        RECT 4.400 237.640 719.620 239.040 ;
        RECT 4.000 232.240 720.020 237.640 ;
        RECT 4.400 230.840 719.620 232.240 ;
        RECT 4.000 225.440 720.020 230.840 ;
        RECT 4.400 224.040 719.620 225.440 ;
        RECT 4.000 218.640 720.020 224.040 ;
        RECT 4.400 217.240 719.620 218.640 ;
        RECT 4.000 215.240 720.020 217.240 ;
        RECT 4.000 213.840 719.620 215.240 ;
        RECT 4.000 211.840 720.020 213.840 ;
        RECT 4.400 210.440 720.020 211.840 ;
        RECT 4.000 208.440 720.020 210.440 ;
        RECT 4.000 207.040 719.620 208.440 ;
        RECT 4.000 205.040 720.020 207.040 ;
        RECT 4.400 203.640 720.020 205.040 ;
        RECT 4.000 201.640 720.020 203.640 ;
        RECT 4.000 200.240 719.620 201.640 ;
        RECT 4.000 198.240 720.020 200.240 ;
        RECT 4.400 196.840 720.020 198.240 ;
        RECT 4.000 194.840 720.020 196.840 ;
        RECT 4.000 193.440 719.620 194.840 ;
        RECT 4.000 191.440 720.020 193.440 ;
        RECT 4.400 190.040 720.020 191.440 ;
        RECT 4.000 188.040 720.020 190.040 ;
        RECT 4.000 186.640 719.620 188.040 ;
        RECT 4.000 184.640 720.020 186.640 ;
        RECT 4.400 183.240 720.020 184.640 ;
        RECT 4.000 181.240 720.020 183.240 ;
        RECT 4.000 179.840 719.620 181.240 ;
        RECT 4.000 177.840 720.020 179.840 ;
        RECT 4.400 176.440 720.020 177.840 ;
        RECT 4.000 174.440 720.020 176.440 ;
        RECT 4.400 173.040 719.620 174.440 ;
        RECT 4.000 167.640 720.020 173.040 ;
        RECT 4.400 166.240 719.620 167.640 ;
        RECT 4.000 160.840 720.020 166.240 ;
        RECT 4.400 159.440 719.620 160.840 ;
        RECT 4.000 154.040 720.020 159.440 ;
        RECT 4.400 152.640 719.620 154.040 ;
        RECT 4.000 147.240 720.020 152.640 ;
        RECT 4.400 145.840 719.620 147.240 ;
        RECT 4.000 140.440 720.020 145.840 ;
        RECT 4.400 139.040 719.620 140.440 ;
        RECT 4.000 133.640 720.020 139.040 ;
        RECT 4.400 132.240 719.620 133.640 ;
        RECT 4.000 130.240 720.020 132.240 ;
        RECT 4.000 128.840 719.620 130.240 ;
        RECT 4.000 126.840 720.020 128.840 ;
        RECT 4.400 125.440 720.020 126.840 ;
        RECT 4.000 123.440 720.020 125.440 ;
        RECT 4.000 122.040 719.620 123.440 ;
        RECT 4.000 120.040 720.020 122.040 ;
        RECT 4.400 118.640 720.020 120.040 ;
        RECT 4.000 116.640 720.020 118.640 ;
        RECT 4.000 115.240 719.620 116.640 ;
        RECT 4.000 113.240 720.020 115.240 ;
        RECT 4.400 111.840 720.020 113.240 ;
        RECT 4.000 109.840 720.020 111.840 ;
        RECT 4.000 108.440 719.620 109.840 ;
        RECT 4.000 106.440 720.020 108.440 ;
        RECT 4.400 105.040 720.020 106.440 ;
        RECT 4.000 103.040 720.020 105.040 ;
        RECT 4.000 101.640 719.620 103.040 ;
        RECT 4.000 99.640 720.020 101.640 ;
        RECT 4.400 98.240 720.020 99.640 ;
        RECT 4.000 96.240 720.020 98.240 ;
        RECT 4.000 94.840 719.620 96.240 ;
        RECT 4.000 92.840 720.020 94.840 ;
        RECT 4.400 91.440 720.020 92.840 ;
        RECT 4.000 89.440 720.020 91.440 ;
        RECT 4.400 88.040 719.620 89.440 ;
        RECT 4.000 82.640 720.020 88.040 ;
        RECT 4.400 81.240 719.620 82.640 ;
        RECT 4.000 75.840 720.020 81.240 ;
        RECT 4.400 74.440 719.620 75.840 ;
        RECT 4.000 69.040 720.020 74.440 ;
        RECT 4.400 67.640 719.620 69.040 ;
        RECT 4.000 62.240 720.020 67.640 ;
        RECT 4.400 60.840 719.620 62.240 ;
        RECT 4.000 55.440 720.020 60.840 ;
        RECT 4.400 54.040 719.620 55.440 ;
        RECT 4.000 48.640 720.020 54.040 ;
        RECT 4.400 47.240 719.620 48.640 ;
        RECT 4.000 45.240 720.020 47.240 ;
        RECT 4.000 43.840 719.620 45.240 ;
        RECT 4.000 41.840 720.020 43.840 ;
        RECT 4.400 40.440 720.020 41.840 ;
        RECT 4.000 38.440 720.020 40.440 ;
        RECT 4.000 37.040 719.620 38.440 ;
        RECT 4.000 35.040 720.020 37.040 ;
        RECT 4.400 33.640 720.020 35.040 ;
        RECT 4.000 31.640 720.020 33.640 ;
        RECT 4.000 30.240 719.620 31.640 ;
        RECT 4.000 28.240 720.020 30.240 ;
        RECT 4.400 26.840 720.020 28.240 ;
        RECT 4.000 24.840 720.020 26.840 ;
        RECT 4.000 23.440 719.620 24.840 ;
        RECT 4.000 21.440 720.020 23.440 ;
        RECT 4.400 20.040 720.020 21.440 ;
        RECT 4.000 18.040 720.020 20.040 ;
        RECT 4.000 16.640 719.620 18.040 ;
        RECT 4.000 14.640 720.020 16.640 ;
        RECT 4.400 13.240 720.020 14.640 ;
        RECT 4.000 11.240 720.020 13.240 ;
        RECT 4.000 9.840 719.620 11.240 ;
        RECT 4.000 7.840 720.020 9.840 ;
        RECT 4.400 6.440 720.020 7.840 ;
        RECT 4.000 4.440 720.020 6.440 ;
        RECT 4.000 3.575 719.620 4.440 ;
      LAYER met4 ;
        RECT 23.295 18.535 97.440 721.305 ;
        RECT 99.840 18.535 174.240 721.305 ;
        RECT 176.640 18.535 251.040 721.305 ;
        RECT 253.440 18.535 327.840 721.305 ;
        RECT 330.240 18.535 404.640 721.305 ;
        RECT 407.040 18.535 481.440 721.305 ;
        RECT 483.840 18.535 558.240 721.305 ;
        RECT 560.640 18.535 601.385 721.305 ;
  END
END fft16_r4
END LIBRARY

